# Placeholder macro written by tools/chip_assembly/macros.py
# kind: tile; a die-assembly tile at 1/4 scale less the die channel; operand in and result out registered at its spine-facing edge (the physical tile's edge registers, ot_chip_v41x_ptile NP stages); routes M2-M7 inside (obstructed), die wiring passes over it on M8/M9
VERSION 5.7 ;
BUSBITCHARS "[]" ;
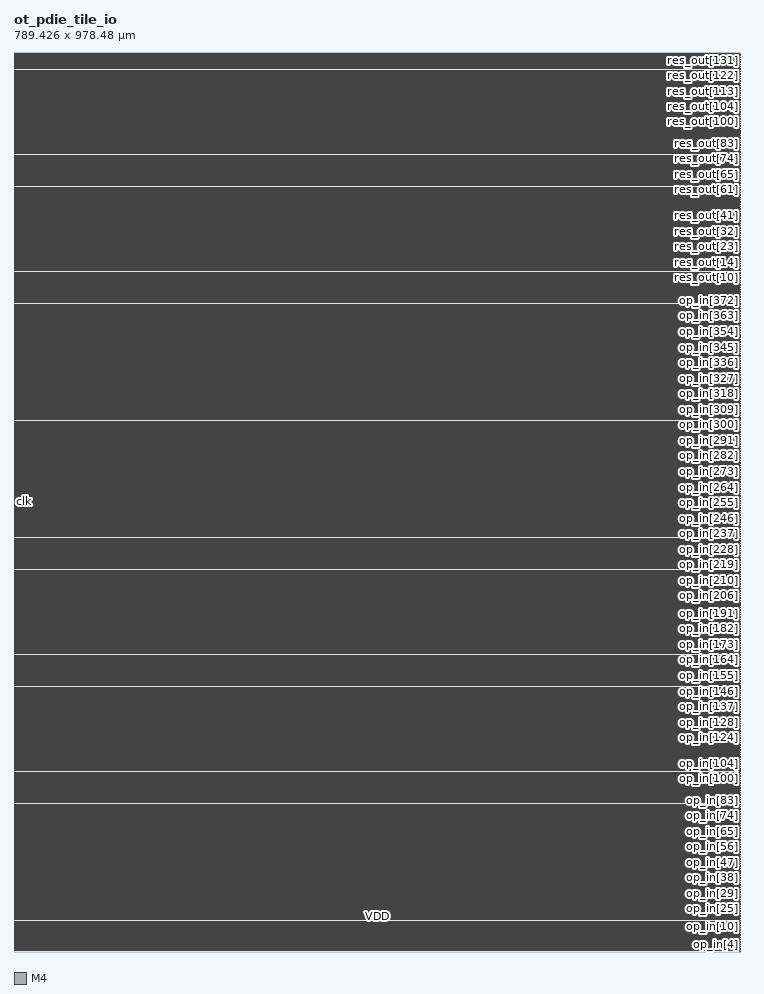
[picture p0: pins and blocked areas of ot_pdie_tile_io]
MACRO ot_pdie_tile_io
  FOREIGN ot_pdie_tile_io 0 0 ;
  SYMMETRY X Y R90 ;
  SIZE 789.426 BY 978.480 ;
  CLASS BLOCK ;
  PIN clk
    DIRECTION INPUT ;
    USE SIGNAL ;
    SHAPE ABUTMENT ;
    PORT
      LAYER M4 ;
      RECT 0.000 489.264 0.192 489.288 ;
    END
  END clk
  PIN op_in[0]
    DIRECTION INPUT ;
    USE SIGNAL ;
    SHAPE ABUTMENT ;
    PORT
      LAYER M4 ;
      RECT 789.234 0.528 789.426 0.552 ;
    END
  END op_in[0]
  PIN op_in[1]
    DIRECTION INPUT ;
    USE SIGNAL ;
    SHAPE ABUTMENT ;
    PORT
      LAYER M4 ;
      RECT 789.234 2.400 789.426 2.424 ;
    END
  END op_in[1]
  PIN op_in[2]
    DIRECTION INPUT ;
    USE SIGNAL ;
    SHAPE ABUTMENT ;
    PORT
      LAYER M4 ;
      RECT 789.234 4.272 789.426 4.296 ;
    END
  END op_in[2]
  PIN op_in[3]
    DIRECTION INPUT ;
    USE SIGNAL ;
    SHAPE ABUTMENT ;
    PORT
      LAYER M4 ;
      RECT 789.234 6.144 789.426 6.168 ;
    END
  END op_in[3]
  PIN op_in[4]
    DIRECTION INPUT ;
    USE SIGNAL ;
    SHAPE ABUTMENT ;
    PORT
      LAYER M4 ;
      RECT 789.234 8.016 789.426 8.040 ;
    END
  END op_in[4]
  PIN op_in[5]
    DIRECTION INPUT ;
    USE SIGNAL ;
    SHAPE ABUTMENT ;
    PORT
      LAYER M4 ;
      RECT 789.234 9.888 789.426 9.912 ;
    END
  END op_in[5]
  PIN op_in[6]
    DIRECTION INPUT ;
    USE SIGNAL ;
    SHAPE ABUTMENT ;
    PORT
      LAYER M4 ;
      RECT 789.234 11.760 789.426 11.784 ;
    END
  END op_in[6]
  PIN op_in[7]
    DIRECTION INPUT ;
    USE SIGNAL ;
    SHAPE ABUTMENT ;
    PORT
      LAYER M4 ;
      RECT 789.234 13.680 789.426 13.704 ;
    END
  END op_in[7]
  PIN op_in[8]
    DIRECTION INPUT ;
    USE SIGNAL ;
    SHAPE ABUTMENT ;
    PORT
      LAYER M4 ;
      RECT 789.234 15.552 789.426 15.576 ;
    END
  END op_in[8]
  PIN op_in[9]
    DIRECTION INPUT ;
    USE SIGNAL ;
    SHAPE ABUTMENT ;
    PORT
      LAYER M4 ;
      RECT 789.234 17.424 789.426 17.448 ;
    END
  END op_in[9]
  PIN op_in[10]
    DIRECTION INPUT ;
    USE SIGNAL ;
    SHAPE ABUTMENT ;
    PORT
      LAYER M4 ;
      RECT 789.234 19.296 789.426 19.320 ;
    END
  END op_in[10]
  PIN op_in[11]
    DIRECTION INPUT ;
    USE SIGNAL ;
    SHAPE ABUTMENT ;
    PORT
      LAYER M4 ;
      RECT 789.234 21.168 789.426 21.192 ;
    END
  END op_in[11]
  PIN op_in[12]
    DIRECTION INPUT ;
    USE SIGNAL ;
    SHAPE ABUTMENT ;
    PORT
      LAYER M4 ;
      RECT 789.234 23.040 789.426 23.064 ;
    END
  END op_in[12]
  PIN op_in[13]
    DIRECTION INPUT ;
    USE SIGNAL ;
    SHAPE ABUTMENT ;
    PORT
      LAYER M4 ;
      RECT 789.234 24.960 789.426 24.984 ;
    END
  END op_in[13]
  PIN op_in[14]
    DIRECTION INPUT ;
    USE SIGNAL ;
    SHAPE ABUTMENT ;
    PORT
      LAYER M4 ;
      RECT 789.234 26.832 789.426 26.856 ;
    END
  END op_in[14]
  PIN op_in[15]
    DIRECTION INPUT ;
    USE SIGNAL ;
    SHAPE ABUTMENT ;
    PORT
      LAYER M4 ;
      RECT 789.234 28.704 789.426 28.728 ;
    END
  END op_in[15]
  PIN op_in[16]
    DIRECTION INPUT ;
    USE SIGNAL ;
    SHAPE ABUTMENT ;
    PORT
      LAYER M4 ;
      RECT 789.234 30.576 789.426 30.600 ;
    END
  END op_in[16]
  PIN op_in[17]
    DIRECTION INPUT ;
    USE SIGNAL ;
    SHAPE ABUTMENT ;
    PORT
      LAYER M4 ;
      RECT 789.234 32.448 789.426 32.472 ;
    END
  END op_in[17]
  PIN op_in[18]
    DIRECTION INPUT ;
    USE SIGNAL ;
    SHAPE ABUTMENT ;
    PORT
      LAYER M4 ;
      RECT 789.234 34.320 789.426 34.344 ;
    END
  END op_in[18]
  PIN op_in[19]
    DIRECTION INPUT ;
    USE SIGNAL ;
    SHAPE ABUTMENT ;
    PORT
      LAYER M4 ;
      RECT 789.234 36.240 789.426 36.264 ;
    END
  END op_in[19]
  PIN op_in[20]
    DIRECTION INPUT ;
    USE SIGNAL ;
    SHAPE ABUTMENT ;
    PORT
      LAYER M4 ;
      RECT 789.234 38.112 789.426 38.136 ;
    END
  END op_in[20]
  PIN op_in[21]
    DIRECTION INPUT ;
    USE SIGNAL ;
    SHAPE ABUTMENT ;
    PORT
      LAYER M4 ;
      RECT 789.234 39.984 789.426 40.008 ;
    END
  END op_in[21]
  PIN op_in[22]
    DIRECTION INPUT ;
    USE SIGNAL ;
    SHAPE ABUTMENT ;
    PORT
      LAYER M4 ;
      RECT 789.234 41.856 789.426 41.880 ;
    END
  END op_in[22]
  PIN op_in[23]
    DIRECTION INPUT ;
    USE SIGNAL ;
    SHAPE ABUTMENT ;
    PORT
      LAYER M4 ;
      RECT 789.234 43.728 789.426 43.752 ;
    END
  END op_in[23]
  PIN op_in[24]
    DIRECTION INPUT ;
    USE SIGNAL ;
    SHAPE ABUTMENT ;
    PORT
      LAYER M4 ;
      RECT 789.234 45.600 789.426 45.624 ;
    END
  END op_in[24]
  PIN op_in[25]
    DIRECTION INPUT ;
    USE SIGNAL ;
    SHAPE ABUTMENT ;
    PORT
      LAYER M4 ;
      RECT 789.234 47.520 789.426 47.544 ;
    END
  END op_in[25]
  PIN op_in[26]
    DIRECTION INPUT ;
    USE SIGNAL ;
    SHAPE ABUTMENT ;
    PORT
      LAYER M4 ;
      RECT 789.234 49.392 789.426 49.416 ;
    END
  END op_in[26]
  PIN op_in[27]
    DIRECTION INPUT ;
    USE SIGNAL ;
    SHAPE ABUTMENT ;
    PORT
      LAYER M4 ;
      RECT 789.234 51.264 789.426 51.288 ;
    END
  END op_in[27]
  PIN op_in[28]
    DIRECTION INPUT ;
    USE SIGNAL ;
    SHAPE ABUTMENT ;
    PORT
      LAYER M4 ;
      RECT 789.234 53.136 789.426 53.160 ;
    END
  END op_in[28]
  PIN op_in[29]
    DIRECTION INPUT ;
    USE SIGNAL ;
    SHAPE ABUTMENT ;
    PORT
      LAYER M4 ;
      RECT 789.234 55.008 789.426 55.032 ;
    END
  END op_in[29]
  PIN op_in[30]
    DIRECTION INPUT ;
    USE SIGNAL ;
    SHAPE ABUTMENT ;
    PORT
      LAYER M4 ;
      RECT 789.234 56.880 789.426 56.904 ;
    END
  END op_in[30]
  PIN op_in[31]
    DIRECTION INPUT ;
    USE SIGNAL ;
    SHAPE ABUTMENT ;
    PORT
      LAYER M4 ;
      RECT 789.234 58.800 789.426 58.824 ;
    END
  END op_in[31]
  PIN op_in[32]
    DIRECTION INPUT ;
    USE SIGNAL ;
    SHAPE ABUTMENT ;
    PORT
      LAYER M4 ;
      RECT 789.234 60.672 789.426 60.696 ;
    END
  END op_in[32]
  PIN op_in[33]
    DIRECTION INPUT ;
    USE SIGNAL ;
    SHAPE ABUTMENT ;
    PORT
      LAYER M4 ;
      RECT 789.234 62.544 789.426 62.568 ;
    END
  END op_in[33]
  PIN op_in[34]
    DIRECTION INPUT ;
    USE SIGNAL ;
    SHAPE ABUTMENT ;
    PORT
      LAYER M4 ;
      RECT 789.234 64.416 789.426 64.440 ;
    END
  END op_in[34]
  PIN op_in[35]
    DIRECTION INPUT ;
    USE SIGNAL ;
    SHAPE ABUTMENT ;
    PORT
      LAYER M4 ;
      RECT 789.234 66.288 789.426 66.312 ;
    END
  END op_in[35]
  PIN op_in[36]
    DIRECTION INPUT ;
    USE SIGNAL ;
    SHAPE ABUTMENT ;
    PORT
      LAYER M4 ;
      RECT 789.234 68.160 789.426 68.184 ;
    END
  END op_in[36]
  PIN op_in[37]
    DIRECTION INPUT ;
    USE SIGNAL ;
    SHAPE ABUTMENT ;
    PORT
      LAYER M4 ;
      RECT 789.234 70.032 789.426 70.056 ;
    END
  END op_in[37]
  PIN op_in[38]
    DIRECTION INPUT ;
    USE SIGNAL ;
    SHAPE ABUTMENT ;
    PORT
      LAYER M4 ;
      RECT 789.234 71.952 789.426 71.976 ;
    END
  END op_in[38]
  PIN op_in[39]
    DIRECTION INPUT ;
    USE SIGNAL ;
    SHAPE ABUTMENT ;
    PORT
      LAYER M4 ;
      RECT 789.234 73.824 789.426 73.848 ;
    END
  END op_in[39]
  PIN op_in[40]
    DIRECTION INPUT ;
    USE SIGNAL ;
    SHAPE ABUTMENT ;
    PORT
      LAYER M4 ;
      RECT 789.234 75.696 789.426 75.720 ;
    END
  END op_in[40]
  PIN op_in[41]
    DIRECTION INPUT ;
    USE SIGNAL ;
    SHAPE ABUTMENT ;
    PORT
      LAYER M4 ;
      RECT 789.234 77.568 789.426 77.592 ;
    END
  END op_in[41]
  PIN op_in[42]
    DIRECTION INPUT ;
    USE SIGNAL ;
    SHAPE ABUTMENT ;
    PORT
      LAYER M4 ;
      RECT 789.234 79.440 789.426 79.464 ;
    END
  END op_in[42]
  PIN op_in[43]
    DIRECTION INPUT ;
    USE SIGNAL ;
    SHAPE ABUTMENT ;
    PORT
      LAYER M4 ;
      RECT 789.234 81.312 789.426 81.336 ;
    END
  END op_in[43]
  PIN op_in[44]
    DIRECTION INPUT ;
    USE SIGNAL ;
    SHAPE ABUTMENT ;
    PORT
      LAYER M4 ;
      RECT 789.234 83.232 789.426 83.256 ;
    END
  END op_in[44]
  PIN op_in[45]
    DIRECTION INPUT ;
    USE SIGNAL ;
    SHAPE ABUTMENT ;
    PORT
      LAYER M4 ;
      RECT 789.234 85.104 789.426 85.128 ;
    END
  END op_in[45]
  PIN op_in[46]
    DIRECTION INPUT ;
    USE SIGNAL ;
    SHAPE ABUTMENT ;
    PORT
      LAYER M4 ;
      RECT 789.234 86.976 789.426 87.000 ;
    END
  END op_in[46]
  PIN op_in[47]
    DIRECTION INPUT ;
    USE SIGNAL ;
    SHAPE ABUTMENT ;
    PORT
      LAYER M4 ;
      RECT 789.234 88.848 789.426 88.872 ;
    END
  END op_in[47]
  PIN op_in[48]
    DIRECTION INPUT ;
    USE SIGNAL ;
    SHAPE ABUTMENT ;
    PORT
      LAYER M4 ;
      RECT 789.234 90.720 789.426 90.744 ;
    END
  END op_in[48]
  PIN op_in[49]
    DIRECTION INPUT ;
    USE SIGNAL ;
    SHAPE ABUTMENT ;
    PORT
      LAYER M4 ;
      RECT 789.234 92.592 789.426 92.616 ;
    END
  END op_in[49]
  PIN op_in[50]
    DIRECTION INPUT ;
    USE SIGNAL ;
    SHAPE ABUTMENT ;
    PORT
      LAYER M4 ;
      RECT 789.234 94.512 789.426 94.536 ;
    END
  END op_in[50]
  PIN op_in[51]
    DIRECTION INPUT ;
    USE SIGNAL ;
    SHAPE ABUTMENT ;
    PORT
      LAYER M4 ;
      RECT 789.234 96.384 789.426 96.408 ;
    END
  END op_in[51]
  PIN op_in[52]
    DIRECTION INPUT ;
    USE SIGNAL ;
    SHAPE ABUTMENT ;
    PORT
      LAYER M4 ;
      RECT 789.234 98.256 789.426 98.280 ;
    END
  END op_in[52]
  PIN op_in[53]
    DIRECTION INPUT ;
    USE SIGNAL ;
    SHAPE ABUTMENT ;
    PORT
      LAYER M4 ;
      RECT 789.234 100.128 789.426 100.152 ;
    END
  END op_in[53]
  PIN op_in[54]
    DIRECTION INPUT ;
    USE SIGNAL ;
    SHAPE ABUTMENT ;
    PORT
      LAYER M4 ;
      RECT 789.234 102.000 789.426 102.024 ;
    END
  END op_in[54]
  PIN op_in[55]
    DIRECTION INPUT ;
    USE SIGNAL ;
    SHAPE ABUTMENT ;
    PORT
      LAYER M4 ;
      RECT 789.234 103.872 789.426 103.896 ;
    END
  END op_in[55]
  PIN op_in[56]
    DIRECTION INPUT ;
    USE SIGNAL ;
    SHAPE ABUTMENT ;
    PORT
      LAYER M4 ;
      RECT 789.234 105.792 789.426 105.816 ;
    END
  END op_in[56]
  PIN op_in[57]
    DIRECTION INPUT ;
    USE SIGNAL ;
    SHAPE ABUTMENT ;
    PORT
      LAYER M4 ;
      RECT 789.234 107.664 789.426 107.688 ;
    END
  END op_in[57]
  PIN op_in[58]
    DIRECTION INPUT ;
    USE SIGNAL ;
    SHAPE ABUTMENT ;
    PORT
      LAYER M4 ;
      RECT 789.234 109.536 789.426 109.560 ;
    END
  END op_in[58]
  PIN op_in[59]
    DIRECTION INPUT ;
    USE SIGNAL ;
    SHAPE ABUTMENT ;
    PORT
      LAYER M4 ;
      RECT 789.234 111.408 789.426 111.432 ;
    END
  END op_in[59]
  PIN op_in[60]
    DIRECTION INPUT ;
    USE SIGNAL ;
    SHAPE ABUTMENT ;
    PORT
      LAYER M4 ;
      RECT 789.234 113.280 789.426 113.304 ;
    END
  END op_in[60]
  PIN op_in[61]
    DIRECTION INPUT ;
    USE SIGNAL ;
    SHAPE ABUTMENT ;
    PORT
      LAYER M4 ;
      RECT 789.234 115.152 789.426 115.176 ;
    END
  END op_in[61]
  PIN op_in[62]
    DIRECTION INPUT ;
    USE SIGNAL ;
    SHAPE ABUTMENT ;
    PORT
      LAYER M4 ;
      RECT 789.234 117.072 789.426 117.096 ;
    END
  END op_in[62]
  PIN op_in[63]
    DIRECTION INPUT ;
    USE SIGNAL ;
    SHAPE ABUTMENT ;
    PORT
      LAYER M4 ;
      RECT 789.234 118.944 789.426 118.968 ;
    END
  END op_in[63]
  PIN op_in[64]
    DIRECTION INPUT ;
    USE SIGNAL ;
    SHAPE ABUTMENT ;
    PORT
      LAYER M4 ;
      RECT 789.234 120.816 789.426 120.840 ;
    END
  END op_in[64]
  PIN op_in[65]
    DIRECTION INPUT ;
    USE SIGNAL ;
    SHAPE ABUTMENT ;
    PORT
      LAYER M4 ;
      RECT 789.234 122.688 789.426 122.712 ;
    END
  END op_in[65]
  PIN op_in[66]
    DIRECTION INPUT ;
    USE SIGNAL ;
    SHAPE ABUTMENT ;
    PORT
      LAYER M4 ;
      RECT 789.234 124.560 789.426 124.584 ;
    END
  END op_in[66]
  PIN op_in[67]
    DIRECTION INPUT ;
    USE SIGNAL ;
    SHAPE ABUTMENT ;
    PORT
      LAYER M4 ;
      RECT 789.234 126.432 789.426 126.456 ;
    END
  END op_in[67]
  PIN op_in[68]
    DIRECTION INPUT ;
    USE SIGNAL ;
    SHAPE ABUTMENT ;
    PORT
      LAYER M4 ;
      RECT 789.234 128.304 789.426 128.328 ;
    END
  END op_in[68]
  PIN op_in[69]
    DIRECTION INPUT ;
    USE SIGNAL ;
    SHAPE ABUTMENT ;
    PORT
      LAYER M4 ;
      RECT 789.234 130.224 789.426 130.248 ;
    END
  END op_in[69]
  PIN op_in[70]
    DIRECTION INPUT ;
    USE SIGNAL ;
    SHAPE ABUTMENT ;
    PORT
      LAYER M4 ;
      RECT 789.234 132.096 789.426 132.120 ;
    END
  END op_in[70]
  PIN op_in[71]
    DIRECTION INPUT ;
    USE SIGNAL ;
    SHAPE ABUTMENT ;
    PORT
      LAYER M4 ;
      RECT 789.234 133.968 789.426 133.992 ;
    END
  END op_in[71]
  PIN op_in[72]
    DIRECTION INPUT ;
    USE SIGNAL ;
    SHAPE ABUTMENT ;
    PORT
      LAYER M4 ;
      RECT 789.234 135.840 789.426 135.864 ;
    END
  END op_in[72]
  PIN op_in[73]
    DIRECTION INPUT ;
    USE SIGNAL ;
    SHAPE ABUTMENT ;
    PORT
      LAYER M4 ;
      RECT 789.234 137.712 789.426 137.736 ;
    END
  END op_in[73]
  PIN op_in[74]
    DIRECTION INPUT ;
    USE SIGNAL ;
    SHAPE ABUTMENT ;
    PORT
      LAYER M4 ;
      RECT 789.234 139.584 789.426 139.608 ;
    END
  END op_in[74]
  PIN op_in[75]
    DIRECTION INPUT ;
    USE SIGNAL ;
    SHAPE ABUTMENT ;
    PORT
      LAYER M4 ;
      RECT 789.234 141.504 789.426 141.528 ;
    END
  END op_in[75]
  PIN op_in[76]
    DIRECTION INPUT ;
    USE SIGNAL ;
    SHAPE ABUTMENT ;
    PORT
      LAYER M4 ;
      RECT 789.234 143.376 789.426 143.400 ;
    END
  END op_in[76]
  PIN op_in[77]
    DIRECTION INPUT ;
    USE SIGNAL ;
    SHAPE ABUTMENT ;
    PORT
      LAYER M4 ;
      RECT 789.234 145.248 789.426 145.272 ;
    END
  END op_in[77]
  PIN op_in[78]
    DIRECTION INPUT ;
    USE SIGNAL ;
    SHAPE ABUTMENT ;
    PORT
      LAYER M4 ;
      RECT 789.234 147.120 789.426 147.144 ;
    END
  END op_in[78]
  PIN op_in[79]
    DIRECTION INPUT ;
    USE SIGNAL ;
    SHAPE ABUTMENT ;
    PORT
      LAYER M4 ;
      RECT 789.234 148.992 789.426 149.016 ;
    END
  END op_in[79]
  PIN op_in[80]
    DIRECTION INPUT ;
    USE SIGNAL ;
    SHAPE ABUTMENT ;
    PORT
      LAYER M4 ;
      RECT 789.234 150.864 789.426 150.888 ;
    END
  END op_in[80]
  PIN op_in[81]
    DIRECTION INPUT ;
    USE SIGNAL ;
    SHAPE ABUTMENT ;
    PORT
      LAYER M4 ;
      RECT 789.234 152.784 789.426 152.808 ;
    END
  END op_in[81]
  PIN op_in[82]
    DIRECTION INPUT ;
    USE SIGNAL ;
    SHAPE ABUTMENT ;
    PORT
      LAYER M4 ;
      RECT 789.234 154.656 789.426 154.680 ;
    END
  END op_in[82]
  PIN op_in[83]
    DIRECTION INPUT ;
    USE SIGNAL ;
    SHAPE ABUTMENT ;
    PORT
      LAYER M4 ;
      RECT 789.234 156.528 789.426 156.552 ;
    END
  END op_in[83]
  PIN op_in[84]
    DIRECTION INPUT ;
    USE SIGNAL ;
    SHAPE ABUTMENT ;
    PORT
      LAYER M4 ;
      RECT 789.234 158.400 789.426 158.424 ;
    END
  END op_in[84]
  PIN op_in[85]
    DIRECTION INPUT ;
    USE SIGNAL ;
    SHAPE ABUTMENT ;
    PORT
      LAYER M4 ;
      RECT 789.234 160.272 789.426 160.296 ;
    END
  END op_in[85]
  PIN op_in[86]
    DIRECTION INPUT ;
    USE SIGNAL ;
    SHAPE ABUTMENT ;
    PORT
      LAYER M4 ;
      RECT 789.234 162.144 789.426 162.168 ;
    END
  END op_in[86]
  PIN op_in[87]
    DIRECTION INPUT ;
    USE SIGNAL ;
    SHAPE ABUTMENT ;
    PORT
      LAYER M4 ;
      RECT 789.234 164.064 789.426 164.088 ;
    END
  END op_in[87]
  PIN op_in[88]
    DIRECTION INPUT ;
    USE SIGNAL ;
    SHAPE ABUTMENT ;
    PORT
      LAYER M4 ;
      RECT 789.234 165.936 789.426 165.960 ;
    END
  END op_in[88]
  PIN op_in[89]
    DIRECTION INPUT ;
    USE SIGNAL ;
    SHAPE ABUTMENT ;
    PORT
      LAYER M4 ;
      RECT 789.234 167.808 789.426 167.832 ;
    END
  END op_in[89]
  PIN op_in[90]
    DIRECTION INPUT ;
    USE SIGNAL ;
    SHAPE ABUTMENT ;
    PORT
      LAYER M4 ;
      RECT 789.234 169.680 789.426 169.704 ;
    END
  END op_in[90]
  PIN op_in[91]
    DIRECTION INPUT ;
    USE SIGNAL ;
    SHAPE ABUTMENT ;
    PORT
      LAYER M4 ;
      RECT 789.234 171.552 789.426 171.576 ;
    END
  END op_in[91]
  PIN op_in[92]
    DIRECTION INPUT ;
    USE SIGNAL ;
    SHAPE ABUTMENT ;
    PORT
      LAYER M4 ;
      RECT 789.234 173.424 789.426 173.448 ;
    END
  END op_in[92]
  PIN op_in[93]
    DIRECTION INPUT ;
    USE SIGNAL ;
    SHAPE ABUTMENT ;
    PORT
      LAYER M4 ;
      RECT 789.234 175.344 789.426 175.368 ;
    END
  END op_in[93]
  PIN op_in[94]
    DIRECTION INPUT ;
    USE SIGNAL ;
    SHAPE ABUTMENT ;
    PORT
      LAYER M4 ;
      RECT 789.234 177.216 789.426 177.240 ;
    END
  END op_in[94]
  PIN op_in[95]
    DIRECTION INPUT ;
    USE SIGNAL ;
    SHAPE ABUTMENT ;
    PORT
      LAYER M4 ;
      RECT 789.234 179.088 789.426 179.112 ;
    END
  END op_in[95]
  PIN op_in[96]
    DIRECTION INPUT ;
    USE SIGNAL ;
    SHAPE ABUTMENT ;
    PORT
      LAYER M4 ;
      RECT 789.234 180.960 789.426 180.984 ;
    END
  END op_in[96]
  PIN op_in[97]
    DIRECTION INPUT ;
    USE SIGNAL ;
    SHAPE ABUTMENT ;
    PORT
      LAYER M4 ;
      RECT 789.234 182.832 789.426 182.856 ;
    END
  END op_in[97]
  PIN op_in[98]
    DIRECTION INPUT ;
    USE SIGNAL ;
    SHAPE ABUTMENT ;
    PORT
      LAYER M4 ;
      RECT 789.234 184.704 789.426 184.728 ;
    END
  END op_in[98]
  PIN op_in[99]
    DIRECTION INPUT ;
    USE SIGNAL ;
    SHAPE ABUTMENT ;
    PORT
      LAYER M4 ;
      RECT 789.234 186.576 789.426 186.600 ;
    END
  END op_in[99]
  PIN op_in[100]
    DIRECTION INPUT ;
    USE SIGNAL ;
    SHAPE ABUTMENT ;
    PORT
      LAYER M4 ;
      RECT 789.234 188.496 789.426 188.520 ;
    END
  END op_in[100]
  PIN op_in[101]
    DIRECTION INPUT ;
    USE SIGNAL ;
    SHAPE ABUTMENT ;
    PORT
      LAYER M4 ;
      RECT 789.234 190.368 789.426 190.392 ;
    END
  END op_in[101]
  PIN op_in[102]
    DIRECTION INPUT ;
    USE SIGNAL ;
    SHAPE ABUTMENT ;
    PORT
      LAYER M4 ;
      RECT 789.234 192.240 789.426 192.264 ;
    END
  END op_in[102]
  PIN op_in[103]
    DIRECTION INPUT ;
    USE SIGNAL ;
    SHAPE ABUTMENT ;
    PORT
      LAYER M4 ;
      RECT 789.234 194.112 789.426 194.136 ;
    END
  END op_in[103]
  PIN op_in[104]
    DIRECTION INPUT ;
    USE SIGNAL ;
    SHAPE ABUTMENT ;
    PORT
      LAYER M4 ;
      RECT 789.234 195.984 789.426 196.008 ;
    END
  END op_in[104]
  PIN op_in[105]
    DIRECTION INPUT ;
    USE SIGNAL ;
    SHAPE ABUTMENT ;
    PORT
      LAYER M4 ;
      RECT 789.234 197.856 789.426 197.880 ;
    END
  END op_in[105]
  PIN op_in[106]
    DIRECTION INPUT ;
    USE SIGNAL ;
    SHAPE ABUTMENT ;
    PORT
      LAYER M4 ;
      RECT 789.234 199.776 789.426 199.800 ;
    END
  END op_in[106]
  PIN op_in[107]
    DIRECTION INPUT ;
    USE SIGNAL ;
    SHAPE ABUTMENT ;
    PORT
      LAYER M4 ;
      RECT 789.234 201.648 789.426 201.672 ;
    END
  END op_in[107]
  PIN op_in[108]
    DIRECTION INPUT ;
    USE SIGNAL ;
    SHAPE ABUTMENT ;
    PORT
      LAYER M4 ;
      RECT 789.234 203.520 789.426 203.544 ;
    END
  END op_in[108]
  PIN op_in[109]
    DIRECTION INPUT ;
    USE SIGNAL ;
    SHAPE ABUTMENT ;
    PORT
      LAYER M4 ;
      RECT 789.234 205.392 789.426 205.416 ;
    END
  END op_in[109]
  PIN op_in[110]
    DIRECTION INPUT ;
    USE SIGNAL ;
    SHAPE ABUTMENT ;
    PORT
      LAYER M4 ;
      RECT 789.234 207.264 789.426 207.288 ;
    END
  END op_in[110]
  PIN op_in[111]
    DIRECTION INPUT ;
    USE SIGNAL ;
    SHAPE ABUTMENT ;
    PORT
      LAYER M4 ;
      RECT 789.234 209.136 789.426 209.160 ;
    END
  END op_in[111]
  PIN op_in[112]
    DIRECTION INPUT ;
    USE SIGNAL ;
    SHAPE ABUTMENT ;
    PORT
      LAYER M4 ;
      RECT 789.234 211.056 789.426 211.080 ;
    END
  END op_in[112]
  PIN op_in[113]
    DIRECTION INPUT ;
    USE SIGNAL ;
    SHAPE ABUTMENT ;
    PORT
      LAYER M4 ;
      RECT 789.234 212.928 789.426 212.952 ;
    END
  END op_in[113]
  PIN op_in[114]
    DIRECTION INPUT ;
    USE SIGNAL ;
    SHAPE ABUTMENT ;
    PORT
      LAYER M4 ;
      RECT 789.234 214.800 789.426 214.824 ;
    END
  END op_in[114]
  PIN op_in[115]
    DIRECTION INPUT ;
    USE SIGNAL ;
    SHAPE ABUTMENT ;
    PORT
      LAYER M4 ;
      RECT 789.234 216.672 789.426 216.696 ;
    END
  END op_in[115]
  PIN op_in[116]
    DIRECTION INPUT ;
    USE SIGNAL ;
    SHAPE ABUTMENT ;
    PORT
      LAYER M4 ;
      RECT 789.234 218.544 789.426 218.568 ;
    END
  END op_in[116]
  PIN op_in[117]
    DIRECTION INPUT ;
    USE SIGNAL ;
    SHAPE ABUTMENT ;
    PORT
      LAYER M4 ;
      RECT 789.234 220.416 789.426 220.440 ;
    END
  END op_in[117]
  PIN op_in[118]
    DIRECTION INPUT ;
    USE SIGNAL ;
    SHAPE ABUTMENT ;
    PORT
      LAYER M4 ;
      RECT 789.234 222.336 789.426 222.360 ;
    END
  END op_in[118]
  PIN op_in[119]
    DIRECTION INPUT ;
    USE SIGNAL ;
    SHAPE ABUTMENT ;
    PORT
      LAYER M4 ;
      RECT 789.234 224.208 789.426 224.232 ;
    END
  END op_in[119]
  PIN op_in[120]
    DIRECTION INPUT ;
    USE SIGNAL ;
    SHAPE ABUTMENT ;
    PORT
      LAYER M4 ;
      RECT 789.234 226.080 789.426 226.104 ;
    END
  END op_in[120]
  PIN op_in[121]
    DIRECTION INPUT ;
    USE SIGNAL ;
    SHAPE ABUTMENT ;
    PORT
      LAYER M4 ;
      RECT 789.234 227.952 789.426 227.976 ;
    END
  END op_in[121]
  PIN op_in[122]
    DIRECTION INPUT ;
    USE SIGNAL ;
    SHAPE ABUTMENT ;
    PORT
      LAYER M4 ;
      RECT 789.234 229.824 789.426 229.848 ;
    END
  END op_in[122]
  PIN op_in[123]
    DIRECTION INPUT ;
    USE SIGNAL ;
    SHAPE ABUTMENT ;
    PORT
      LAYER M4 ;
      RECT 789.234 231.696 789.426 231.720 ;
    END
  END op_in[123]
  PIN op_in[124]
    DIRECTION INPUT ;
    USE SIGNAL ;
    SHAPE ABUTMENT ;
    PORT
      LAYER M4 ;
      RECT 789.234 233.616 789.426 233.640 ;
    END
  END op_in[124]
  PIN op_in[125]
    DIRECTION INPUT ;
    USE SIGNAL ;
    SHAPE ABUTMENT ;
    PORT
      LAYER M4 ;
      RECT 789.234 235.488 789.426 235.512 ;
    END
  END op_in[125]
  PIN op_in[126]
    DIRECTION INPUT ;
    USE SIGNAL ;
    SHAPE ABUTMENT ;
    PORT
      LAYER M4 ;
      RECT 789.234 237.360 789.426 237.384 ;
    END
  END op_in[126]
  PIN op_in[127]
    DIRECTION INPUT ;
    USE SIGNAL ;
    SHAPE ABUTMENT ;
    PORT
      LAYER M4 ;
      RECT 789.234 239.232 789.426 239.256 ;
    END
  END op_in[127]
  PIN op_in[128]
    DIRECTION INPUT ;
    USE SIGNAL ;
    SHAPE ABUTMENT ;
    PORT
      LAYER M4 ;
      RECT 789.234 241.104 789.426 241.128 ;
    END
  END op_in[128]
  PIN op_in[129]
    DIRECTION INPUT ;
    USE SIGNAL ;
    SHAPE ABUTMENT ;
    PORT
      LAYER M4 ;
      RECT 789.234 242.976 789.426 243.000 ;
    END
  END op_in[129]
  PIN op_in[130]
    DIRECTION INPUT ;
    USE SIGNAL ;
    SHAPE ABUTMENT ;
    PORT
      LAYER M4 ;
      RECT 789.234 244.896 789.426 244.920 ;
    END
  END op_in[130]
  PIN op_in[131]
    DIRECTION INPUT ;
    USE SIGNAL ;
    SHAPE ABUTMENT ;
    PORT
      LAYER M4 ;
      RECT 789.234 246.768 789.426 246.792 ;
    END
  END op_in[131]
  PIN op_in[132]
    DIRECTION INPUT ;
    USE SIGNAL ;
    SHAPE ABUTMENT ;
    PORT
      LAYER M4 ;
      RECT 789.234 248.640 789.426 248.664 ;
    END
  END op_in[132]
  PIN op_in[133]
    DIRECTION INPUT ;
    USE SIGNAL ;
    SHAPE ABUTMENT ;
    PORT
      LAYER M4 ;
      RECT 789.234 250.512 789.426 250.536 ;
    END
  END op_in[133]
  PIN op_in[134]
    DIRECTION INPUT ;
    USE SIGNAL ;
    SHAPE ABUTMENT ;
    PORT
      LAYER M4 ;
      RECT 789.234 252.384 789.426 252.408 ;
    END
  END op_in[134]
  PIN op_in[135]
    DIRECTION INPUT ;
    USE SIGNAL ;
    SHAPE ABUTMENT ;
    PORT
      LAYER M4 ;
      RECT 789.234 254.256 789.426 254.280 ;
    END
  END op_in[135]
  PIN op_in[136]
    DIRECTION INPUT ;
    USE SIGNAL ;
    SHAPE ABUTMENT ;
    PORT
      LAYER M4 ;
      RECT 789.234 256.128 789.426 256.152 ;
    END
  END op_in[136]
  PIN op_in[137]
    DIRECTION INPUT ;
    USE SIGNAL ;
    SHAPE ABUTMENT ;
    PORT
      LAYER M4 ;
      RECT 789.234 258.048 789.426 258.072 ;
    END
  END op_in[137]
  PIN op_in[138]
    DIRECTION INPUT ;
    USE SIGNAL ;
    SHAPE ABUTMENT ;
    PORT
      LAYER M4 ;
      RECT 789.234 259.920 789.426 259.944 ;
    END
  END op_in[138]
  PIN op_in[139]
    DIRECTION INPUT ;
    USE SIGNAL ;
    SHAPE ABUTMENT ;
    PORT
      LAYER M4 ;
      RECT 789.234 261.792 789.426 261.816 ;
    END
  END op_in[139]
  PIN op_in[140]
    DIRECTION INPUT ;
    USE SIGNAL ;
    SHAPE ABUTMENT ;
    PORT
      LAYER M4 ;
      RECT 789.234 263.664 789.426 263.688 ;
    END
  END op_in[140]
  PIN op_in[141]
    DIRECTION INPUT ;
    USE SIGNAL ;
    SHAPE ABUTMENT ;
    PORT
      LAYER M4 ;
      RECT 789.234 265.536 789.426 265.560 ;
    END
  END op_in[141]
  PIN op_in[142]
    DIRECTION INPUT ;
    USE SIGNAL ;
    SHAPE ABUTMENT ;
    PORT
      LAYER M4 ;
      RECT 789.234 267.408 789.426 267.432 ;
    END
  END op_in[142]
  PIN op_in[143]
    DIRECTION INPUT ;
    USE SIGNAL ;
    SHAPE ABUTMENT ;
    PORT
      LAYER M4 ;
      RECT 789.234 269.328 789.426 269.352 ;
    END
  END op_in[143]
  PIN op_in[144]
    DIRECTION INPUT ;
    USE SIGNAL ;
    SHAPE ABUTMENT ;
    PORT
      LAYER M4 ;
      RECT 789.234 271.200 789.426 271.224 ;
    END
  END op_in[144]
  PIN op_in[145]
    DIRECTION INPUT ;
    USE SIGNAL ;
    SHAPE ABUTMENT ;
    PORT
      LAYER M4 ;
      RECT 789.234 273.072 789.426 273.096 ;
    END
  END op_in[145]
  PIN op_in[146]
    DIRECTION INPUT ;
    USE SIGNAL ;
    SHAPE ABUTMENT ;
    PORT
      LAYER M4 ;
      RECT 789.234 274.944 789.426 274.968 ;
    END
  END op_in[146]
  PIN op_in[147]
    DIRECTION INPUT ;
    USE SIGNAL ;
    SHAPE ABUTMENT ;
    PORT
      LAYER M4 ;
      RECT 789.234 276.816 789.426 276.840 ;
    END
  END op_in[147]
  PIN op_in[148]
    DIRECTION INPUT ;
    USE SIGNAL ;
    SHAPE ABUTMENT ;
    PORT
      LAYER M4 ;
      RECT 789.234 278.688 789.426 278.712 ;
    END
  END op_in[148]
  PIN op_in[149]
    DIRECTION INPUT ;
    USE SIGNAL ;
    SHAPE ABUTMENT ;
    PORT
      LAYER M4 ;
      RECT 789.234 280.608 789.426 280.632 ;
    END
  END op_in[149]
  PIN op_in[150]
    DIRECTION INPUT ;
    USE SIGNAL ;
    SHAPE ABUTMENT ;
    PORT
      LAYER M4 ;
      RECT 789.234 282.480 789.426 282.504 ;
    END
  END op_in[150]
  PIN op_in[151]
    DIRECTION INPUT ;
    USE SIGNAL ;
    SHAPE ABUTMENT ;
    PORT
      LAYER M4 ;
      RECT 789.234 284.352 789.426 284.376 ;
    END
  END op_in[151]
  PIN op_in[152]
    DIRECTION INPUT ;
    USE SIGNAL ;
    SHAPE ABUTMENT ;
    PORT
      LAYER M4 ;
      RECT 789.234 286.224 789.426 286.248 ;
    END
  END op_in[152]
  PIN op_in[153]
    DIRECTION INPUT ;
    USE SIGNAL ;
    SHAPE ABUTMENT ;
    PORT
      LAYER M4 ;
      RECT 789.234 288.096 789.426 288.120 ;
    END
  END op_in[153]
  PIN op_in[154]
    DIRECTION INPUT ;
    USE SIGNAL ;
    SHAPE ABUTMENT ;
    PORT
      LAYER M4 ;
      RECT 789.234 289.968 789.426 289.992 ;
    END
  END op_in[154]
  PIN op_in[155]
    DIRECTION INPUT ;
    USE SIGNAL ;
    SHAPE ABUTMENT ;
    PORT
      LAYER M4 ;
      RECT 789.234 291.888 789.426 291.912 ;
    END
  END op_in[155]
  PIN op_in[156]
    DIRECTION INPUT ;
    USE SIGNAL ;
    SHAPE ABUTMENT ;
    PORT
      LAYER M4 ;
      RECT 789.234 293.760 789.426 293.784 ;
    END
  END op_in[156]
  PIN op_in[157]
    DIRECTION INPUT ;
    USE SIGNAL ;
    SHAPE ABUTMENT ;
    PORT
      LAYER M4 ;
      RECT 789.234 295.632 789.426 295.656 ;
    END
  END op_in[157]
  PIN op_in[158]
    DIRECTION INPUT ;
    USE SIGNAL ;
    SHAPE ABUTMENT ;
    PORT
      LAYER M4 ;
      RECT 789.234 297.504 789.426 297.528 ;
    END
  END op_in[158]
  PIN op_in[159]
    DIRECTION INPUT ;
    USE SIGNAL ;
    SHAPE ABUTMENT ;
    PORT
      LAYER M4 ;
      RECT 789.234 299.376 789.426 299.400 ;
    END
  END op_in[159]
  PIN op_in[160]
    DIRECTION INPUT ;
    USE SIGNAL ;
    SHAPE ABUTMENT ;
    PORT
      LAYER M4 ;
      RECT 789.234 301.248 789.426 301.272 ;
    END
  END op_in[160]
  PIN op_in[161]
    DIRECTION INPUT ;
    USE SIGNAL ;
    SHAPE ABUTMENT ;
    PORT
      LAYER M4 ;
      RECT 789.234 303.168 789.426 303.192 ;
    END
  END op_in[161]
  PIN op_in[162]
    DIRECTION INPUT ;
    USE SIGNAL ;
    SHAPE ABUTMENT ;
    PORT
      LAYER M4 ;
      RECT 789.234 305.040 789.426 305.064 ;
    END
  END op_in[162]
  PIN op_in[163]
    DIRECTION INPUT ;
    USE SIGNAL ;
    SHAPE ABUTMENT ;
    PORT
      LAYER M4 ;
      RECT 789.234 306.912 789.426 306.936 ;
    END
  END op_in[163]
  PIN op_in[164]
    DIRECTION INPUT ;
    USE SIGNAL ;
    SHAPE ABUTMENT ;
    PORT
      LAYER M4 ;
      RECT 789.234 308.784 789.426 308.808 ;
    END
  END op_in[164]
  PIN op_in[165]
    DIRECTION INPUT ;
    USE SIGNAL ;
    SHAPE ABUTMENT ;
    PORT
      LAYER M4 ;
      RECT 789.234 310.656 789.426 310.680 ;
    END
  END op_in[165]
  PIN op_in[166]
    DIRECTION INPUT ;
    USE SIGNAL ;
    SHAPE ABUTMENT ;
    PORT
      LAYER M4 ;
      RECT 789.234 312.528 789.426 312.552 ;
    END
  END op_in[166]
  PIN op_in[167]
    DIRECTION INPUT ;
    USE SIGNAL ;
    SHAPE ABUTMENT ;
    PORT
      LAYER M4 ;
      RECT 789.234 314.400 789.426 314.424 ;
    END
  END op_in[167]
  PIN op_in[168]
    DIRECTION INPUT ;
    USE SIGNAL ;
    SHAPE ABUTMENT ;
    PORT
      LAYER M4 ;
      RECT 789.234 316.320 789.426 316.344 ;
    END
  END op_in[168]
  PIN op_in[169]
    DIRECTION INPUT ;
    USE SIGNAL ;
    SHAPE ABUTMENT ;
    PORT
      LAYER M4 ;
      RECT 789.234 318.192 789.426 318.216 ;
    END
  END op_in[169]
  PIN op_in[170]
    DIRECTION INPUT ;
    USE SIGNAL ;
    SHAPE ABUTMENT ;
    PORT
      LAYER M4 ;
      RECT 789.234 320.064 789.426 320.088 ;
    END
  END op_in[170]
  PIN op_in[171]
    DIRECTION INPUT ;
    USE SIGNAL ;
    SHAPE ABUTMENT ;
    PORT
      LAYER M4 ;
      RECT 789.234 321.936 789.426 321.960 ;
    END
  END op_in[171]
  PIN op_in[172]
    DIRECTION INPUT ;
    USE SIGNAL ;
    SHAPE ABUTMENT ;
    PORT
      LAYER M4 ;
      RECT 789.234 323.808 789.426 323.832 ;
    END
  END op_in[172]
  PIN op_in[173]
    DIRECTION INPUT ;
    USE SIGNAL ;
    SHAPE ABUTMENT ;
    PORT
      LAYER M4 ;
      RECT 789.234 325.680 789.426 325.704 ;
    END
  END op_in[173]
  PIN op_in[174]
    DIRECTION INPUT ;
    USE SIGNAL ;
    SHAPE ABUTMENT ;
    PORT
      LAYER M4 ;
      RECT 789.234 327.600 789.426 327.624 ;
    END
  END op_in[174]
  PIN op_in[175]
    DIRECTION INPUT ;
    USE SIGNAL ;
    SHAPE ABUTMENT ;
    PORT
      LAYER M4 ;
      RECT 789.234 329.472 789.426 329.496 ;
    END
  END op_in[175]
  PIN op_in[176]
    DIRECTION INPUT ;
    USE SIGNAL ;
    SHAPE ABUTMENT ;
    PORT
      LAYER M4 ;
      RECT 789.234 331.344 789.426 331.368 ;
    END
  END op_in[176]
  PIN op_in[177]
    DIRECTION INPUT ;
    USE SIGNAL ;
    SHAPE ABUTMENT ;
    PORT
      LAYER M4 ;
      RECT 789.234 333.216 789.426 333.240 ;
    END
  END op_in[177]
  PIN op_in[178]
    DIRECTION INPUT ;
    USE SIGNAL ;
    SHAPE ABUTMENT ;
    PORT
      LAYER M4 ;
      RECT 789.234 335.088 789.426 335.112 ;
    END
  END op_in[178]
  PIN op_in[179]
    DIRECTION INPUT ;
    USE SIGNAL ;
    SHAPE ABUTMENT ;
    PORT
      LAYER M4 ;
      RECT 789.234 336.960 789.426 336.984 ;
    END
  END op_in[179]
  PIN op_in[180]
    DIRECTION INPUT ;
    USE SIGNAL ;
    SHAPE ABUTMENT ;
    PORT
      LAYER M4 ;
      RECT 789.234 338.880 789.426 338.904 ;
    END
  END op_in[180]
  PIN op_in[181]
    DIRECTION INPUT ;
    USE SIGNAL ;
    SHAPE ABUTMENT ;
    PORT
      LAYER M4 ;
      RECT 789.234 340.752 789.426 340.776 ;
    END
  END op_in[181]
  PIN op_in[182]
    DIRECTION INPUT ;
    USE SIGNAL ;
    SHAPE ABUTMENT ;
    PORT
      LAYER M4 ;
      RECT 789.234 342.624 789.426 342.648 ;
    END
  END op_in[182]
  PIN op_in[183]
    DIRECTION INPUT ;
    USE SIGNAL ;
    SHAPE ABUTMENT ;
    PORT
      LAYER M4 ;
      RECT 789.234 344.496 789.426 344.520 ;
    END
  END op_in[183]
  PIN op_in[184]
    DIRECTION INPUT ;
    USE SIGNAL ;
    SHAPE ABUTMENT ;
    PORT
      LAYER M4 ;
      RECT 789.234 346.368 789.426 346.392 ;
    END
  END op_in[184]
  PIN op_in[185]
    DIRECTION INPUT ;
    USE SIGNAL ;
    SHAPE ABUTMENT ;
    PORT
      LAYER M4 ;
      RECT 789.234 348.240 789.426 348.264 ;
    END
  END op_in[185]
  PIN op_in[186]
    DIRECTION INPUT ;
    USE SIGNAL ;
    SHAPE ABUTMENT ;
    PORT
      LAYER M4 ;
      RECT 789.234 350.160 789.426 350.184 ;
    END
  END op_in[186]
  PIN op_in[187]
    DIRECTION INPUT ;
    USE SIGNAL ;
    SHAPE ABUTMENT ;
    PORT
      LAYER M4 ;
      RECT 789.234 352.032 789.426 352.056 ;
    END
  END op_in[187]
  PIN op_in[188]
    DIRECTION INPUT ;
    USE SIGNAL ;
    SHAPE ABUTMENT ;
    PORT
      LAYER M4 ;
      RECT 789.234 353.904 789.426 353.928 ;
    END
  END op_in[188]
  PIN op_in[189]
    DIRECTION INPUT ;
    USE SIGNAL ;
    SHAPE ABUTMENT ;
    PORT
      LAYER M4 ;
      RECT 789.234 355.776 789.426 355.800 ;
    END
  END op_in[189]
  PIN op_in[190]
    DIRECTION INPUT ;
    USE SIGNAL ;
    SHAPE ABUTMENT ;
    PORT
      LAYER M4 ;
      RECT 789.234 357.648 789.426 357.672 ;
    END
  END op_in[190]
  PIN op_in[191]
    DIRECTION INPUT ;
    USE SIGNAL ;
    SHAPE ABUTMENT ;
    PORT
      LAYER M4 ;
      RECT 789.234 359.520 789.426 359.544 ;
    END
  END op_in[191]
  PIN op_in[192]
    DIRECTION INPUT ;
    USE SIGNAL ;
    SHAPE ABUTMENT ;
    PORT
      LAYER M4 ;
      RECT 789.234 361.440 789.426 361.464 ;
    END
  END op_in[192]
  PIN op_in[193]
    DIRECTION INPUT ;
    USE SIGNAL ;
    SHAPE ABUTMENT ;
    PORT
      LAYER M4 ;
      RECT 789.234 363.312 789.426 363.336 ;
    END
  END op_in[193]
  PIN op_in[194]
    DIRECTION INPUT ;
    USE SIGNAL ;
    SHAPE ABUTMENT ;
    PORT
      LAYER M4 ;
      RECT 789.234 365.184 789.426 365.208 ;
    END
  END op_in[194]
  PIN op_in[195]
    DIRECTION INPUT ;
    USE SIGNAL ;
    SHAPE ABUTMENT ;
    PORT
      LAYER M4 ;
      RECT 789.234 367.056 789.426 367.080 ;
    END
  END op_in[195]
  PIN op_in[196]
    DIRECTION INPUT ;
    USE SIGNAL ;
    SHAPE ABUTMENT ;
    PORT
      LAYER M4 ;
      RECT 789.234 368.928 789.426 368.952 ;
    END
  END op_in[196]
  PIN op_in[197]
    DIRECTION INPUT ;
    USE SIGNAL ;
    SHAPE ABUTMENT ;
    PORT
      LAYER M4 ;
      RECT 789.234 370.800 789.426 370.824 ;
    END
  END op_in[197]
  PIN op_in[198]
    DIRECTION INPUT ;
    USE SIGNAL ;
    SHAPE ABUTMENT ;
    PORT
      LAYER M4 ;
      RECT 789.234 372.672 789.426 372.696 ;
    END
  END op_in[198]
  PIN op_in[199]
    DIRECTION INPUT ;
    USE SIGNAL ;
    SHAPE ABUTMENT ;
    PORT
      LAYER M4 ;
      RECT 789.234 374.592 789.426 374.616 ;
    END
  END op_in[199]
  PIN op_in[200]
    DIRECTION INPUT ;
    USE SIGNAL ;
    SHAPE ABUTMENT ;
    PORT
      LAYER M4 ;
      RECT 789.234 376.464 789.426 376.488 ;
    END
  END op_in[200]
  PIN op_in[201]
    DIRECTION INPUT ;
    USE SIGNAL ;
    SHAPE ABUTMENT ;
    PORT
      LAYER M4 ;
      RECT 789.234 378.336 789.426 378.360 ;
    END
  END op_in[201]
  PIN op_in[202]
    DIRECTION INPUT ;
    USE SIGNAL ;
    SHAPE ABUTMENT ;
    PORT
      LAYER M4 ;
      RECT 789.234 380.208 789.426 380.232 ;
    END
  END op_in[202]
  PIN op_in[203]
    DIRECTION INPUT ;
    USE SIGNAL ;
    SHAPE ABUTMENT ;
    PORT
      LAYER M4 ;
      RECT 789.234 382.080 789.426 382.104 ;
    END
  END op_in[203]
  PIN op_in[204]
    DIRECTION INPUT ;
    USE SIGNAL ;
    SHAPE ABUTMENT ;
    PORT
      LAYER M4 ;
      RECT 789.234 383.952 789.426 383.976 ;
    END
  END op_in[204]
  PIN op_in[205]
    DIRECTION INPUT ;
    USE SIGNAL ;
    SHAPE ABUTMENT ;
    PORT
      LAYER M4 ;
      RECT 789.234 385.872 789.426 385.896 ;
    END
  END op_in[205]
  PIN op_in[206]
    DIRECTION INPUT ;
    USE SIGNAL ;
    SHAPE ABUTMENT ;
    PORT
      LAYER M4 ;
      RECT 789.234 387.744 789.426 387.768 ;
    END
  END op_in[206]
  PIN op_in[207]
    DIRECTION INPUT ;
    USE SIGNAL ;
    SHAPE ABUTMENT ;
    PORT
      LAYER M4 ;
      RECT 789.234 389.616 789.426 389.640 ;
    END
  END op_in[207]
  PIN op_in[208]
    DIRECTION INPUT ;
    USE SIGNAL ;
    SHAPE ABUTMENT ;
    PORT
      LAYER M4 ;
      RECT 789.234 391.488 789.426 391.512 ;
    END
  END op_in[208]
  PIN op_in[209]
    DIRECTION INPUT ;
    USE SIGNAL ;
    SHAPE ABUTMENT ;
    PORT
      LAYER M4 ;
      RECT 789.234 393.360 789.426 393.384 ;
    END
  END op_in[209]
  PIN op_in[210]
    DIRECTION INPUT ;
    USE SIGNAL ;
    SHAPE ABUTMENT ;
    PORT
      LAYER M4 ;
      RECT 789.234 395.232 789.426 395.256 ;
    END
  END op_in[210]
  PIN op_in[211]
    DIRECTION INPUT ;
    USE SIGNAL ;
    SHAPE ABUTMENT ;
    PORT
      LAYER M4 ;
      RECT 789.234 397.152 789.426 397.176 ;
    END
  END op_in[211]
  PIN op_in[212]
    DIRECTION INPUT ;
    USE SIGNAL ;
    SHAPE ABUTMENT ;
    PORT
      LAYER M4 ;
      RECT 789.234 399.024 789.426 399.048 ;
    END
  END op_in[212]
  PIN op_in[213]
    DIRECTION INPUT ;
    USE SIGNAL ;
    SHAPE ABUTMENT ;
    PORT
      LAYER M4 ;
      RECT 789.234 400.896 789.426 400.920 ;
    END
  END op_in[213]
  PIN op_in[214]
    DIRECTION INPUT ;
    USE SIGNAL ;
    SHAPE ABUTMENT ;
    PORT
      LAYER M4 ;
      RECT 789.234 402.768 789.426 402.792 ;
    END
  END op_in[214]
  PIN op_in[215]
    DIRECTION INPUT ;
    USE SIGNAL ;
    SHAPE ABUTMENT ;
    PORT
      LAYER M4 ;
      RECT 789.234 404.640 789.426 404.664 ;
    END
  END op_in[215]
  PIN op_in[216]
    DIRECTION INPUT ;
    USE SIGNAL ;
    SHAPE ABUTMENT ;
    PORT
      LAYER M4 ;
      RECT 789.234 406.512 789.426 406.536 ;
    END
  END op_in[216]
  PIN op_in[217]
    DIRECTION INPUT ;
    USE SIGNAL ;
    SHAPE ABUTMENT ;
    PORT
      LAYER M4 ;
      RECT 789.234 408.432 789.426 408.456 ;
    END
  END op_in[217]
  PIN op_in[218]
    DIRECTION INPUT ;
    USE SIGNAL ;
    SHAPE ABUTMENT ;
    PORT
      LAYER M4 ;
      RECT 789.234 410.304 789.426 410.328 ;
    END
  END op_in[218]
  PIN op_in[219]
    DIRECTION INPUT ;
    USE SIGNAL ;
    SHAPE ABUTMENT ;
    PORT
      LAYER M4 ;
      RECT 789.234 412.176 789.426 412.200 ;
    END
  END op_in[219]
  PIN op_in[220]
    DIRECTION INPUT ;
    USE SIGNAL ;
    SHAPE ABUTMENT ;
    PORT
      LAYER M4 ;
      RECT 789.234 414.048 789.426 414.072 ;
    END
  END op_in[220]
  PIN op_in[221]
    DIRECTION INPUT ;
    USE SIGNAL ;
    SHAPE ABUTMENT ;
    PORT
      LAYER M4 ;
      RECT 789.234 415.920 789.426 415.944 ;
    END
  END op_in[221]
  PIN op_in[222]
    DIRECTION INPUT ;
    USE SIGNAL ;
    SHAPE ABUTMENT ;
    PORT
      LAYER M4 ;
      RECT 789.234 417.792 789.426 417.816 ;
    END
  END op_in[222]
  PIN op_in[223]
    DIRECTION INPUT ;
    USE SIGNAL ;
    SHAPE ABUTMENT ;
    PORT
      LAYER M4 ;
      RECT 789.234 419.712 789.426 419.736 ;
    END
  END op_in[223]
  PIN op_in[224]
    DIRECTION INPUT ;
    USE SIGNAL ;
    SHAPE ABUTMENT ;
    PORT
      LAYER M4 ;
      RECT 789.234 421.584 789.426 421.608 ;
    END
  END op_in[224]
  PIN op_in[225]
    DIRECTION INPUT ;
    USE SIGNAL ;
    SHAPE ABUTMENT ;
    PORT
      LAYER M4 ;
      RECT 789.234 423.456 789.426 423.480 ;
    END
  END op_in[225]
  PIN op_in[226]
    DIRECTION INPUT ;
    USE SIGNAL ;
    SHAPE ABUTMENT ;
    PORT
      LAYER M4 ;
      RECT 789.234 425.328 789.426 425.352 ;
    END
  END op_in[226]
  PIN op_in[227]
    DIRECTION INPUT ;
    USE SIGNAL ;
    SHAPE ABUTMENT ;
    PORT
      LAYER M4 ;
      RECT 789.234 427.200 789.426 427.224 ;
    END
  END op_in[227]
  PIN op_in[228]
    DIRECTION INPUT ;
    USE SIGNAL ;
    SHAPE ABUTMENT ;
    PORT
      LAYER M4 ;
      RECT 789.234 429.072 789.426 429.096 ;
    END
  END op_in[228]
  PIN op_in[229]
    DIRECTION INPUT ;
    USE SIGNAL ;
    SHAPE ABUTMENT ;
    PORT
      LAYER M4 ;
      RECT 789.234 430.944 789.426 430.968 ;
    END
  END op_in[229]
  PIN op_in[230]
    DIRECTION INPUT ;
    USE SIGNAL ;
    SHAPE ABUTMENT ;
    PORT
      LAYER M4 ;
      RECT 789.234 432.864 789.426 432.888 ;
    END
  END op_in[230]
  PIN op_in[231]
    DIRECTION INPUT ;
    USE SIGNAL ;
    SHAPE ABUTMENT ;
    PORT
      LAYER M4 ;
      RECT 789.234 434.736 789.426 434.760 ;
    END
  END op_in[231]
  PIN op_in[232]
    DIRECTION INPUT ;
    USE SIGNAL ;
    SHAPE ABUTMENT ;
    PORT
      LAYER M4 ;
      RECT 789.234 436.608 789.426 436.632 ;
    END
  END op_in[232]
  PIN op_in[233]
    DIRECTION INPUT ;
    USE SIGNAL ;
    SHAPE ABUTMENT ;
    PORT
      LAYER M4 ;
      RECT 789.234 438.480 789.426 438.504 ;
    END
  END op_in[233]
  PIN op_in[234]
    DIRECTION INPUT ;
    USE SIGNAL ;
    SHAPE ABUTMENT ;
    PORT
      LAYER M4 ;
      RECT 789.234 440.352 789.426 440.376 ;
    END
  END op_in[234]
  PIN op_in[235]
    DIRECTION INPUT ;
    USE SIGNAL ;
    SHAPE ABUTMENT ;
    PORT
      LAYER M4 ;
      RECT 789.234 442.224 789.426 442.248 ;
    END
  END op_in[235]
  PIN op_in[236]
    DIRECTION INPUT ;
    USE SIGNAL ;
    SHAPE ABUTMENT ;
    PORT
      LAYER M4 ;
      RECT 789.234 444.144 789.426 444.168 ;
    END
  END op_in[236]
  PIN op_in[237]
    DIRECTION INPUT ;
    USE SIGNAL ;
    SHAPE ABUTMENT ;
    PORT
      LAYER M4 ;
      RECT 789.234 446.016 789.426 446.040 ;
    END
  END op_in[237]
  PIN op_in[238]
    DIRECTION INPUT ;
    USE SIGNAL ;
    SHAPE ABUTMENT ;
    PORT
      LAYER M4 ;
      RECT 789.234 447.888 789.426 447.912 ;
    END
  END op_in[238]
  PIN op_in[239]
    DIRECTION INPUT ;
    USE SIGNAL ;
    SHAPE ABUTMENT ;
    PORT
      LAYER M4 ;
      RECT 789.234 449.760 789.426 449.784 ;
    END
  END op_in[239]
  PIN op_in[240]
    DIRECTION INPUT ;
    USE SIGNAL ;
    SHAPE ABUTMENT ;
    PORT
      LAYER M4 ;
      RECT 789.234 451.632 789.426 451.656 ;
    END
  END op_in[240]
  PIN op_in[241]
    DIRECTION INPUT ;
    USE SIGNAL ;
    SHAPE ABUTMENT ;
    PORT
      LAYER M4 ;
      RECT 789.234 453.504 789.426 453.528 ;
    END
  END op_in[241]
  PIN op_in[242]
    DIRECTION INPUT ;
    USE SIGNAL ;
    SHAPE ABUTMENT ;
    PORT
      LAYER M4 ;
      RECT 789.234 455.424 789.426 455.448 ;
    END
  END op_in[242]
  PIN op_in[243]
    DIRECTION INPUT ;
    USE SIGNAL ;
    SHAPE ABUTMENT ;
    PORT
      LAYER M4 ;
      RECT 789.234 457.296 789.426 457.320 ;
    END
  END op_in[243]
  PIN op_in[244]
    DIRECTION INPUT ;
    USE SIGNAL ;
    SHAPE ABUTMENT ;
    PORT
      LAYER M4 ;
      RECT 789.234 459.168 789.426 459.192 ;
    END
  END op_in[244]
  PIN op_in[245]
    DIRECTION INPUT ;
    USE SIGNAL ;
    SHAPE ABUTMENT ;
    PORT
      LAYER M4 ;
      RECT 789.234 461.040 789.426 461.064 ;
    END
  END op_in[245]
  PIN op_in[246]
    DIRECTION INPUT ;
    USE SIGNAL ;
    SHAPE ABUTMENT ;
    PORT
      LAYER M4 ;
      RECT 789.234 462.912 789.426 462.936 ;
    END
  END op_in[246]
  PIN op_in[247]
    DIRECTION INPUT ;
    USE SIGNAL ;
    SHAPE ABUTMENT ;
    PORT
      LAYER M4 ;
      RECT 789.234 464.784 789.426 464.808 ;
    END
  END op_in[247]
  PIN op_in[248]
    DIRECTION INPUT ;
    USE SIGNAL ;
    SHAPE ABUTMENT ;
    PORT
      LAYER M4 ;
      RECT 789.234 466.704 789.426 466.728 ;
    END
  END op_in[248]
  PIN op_in[249]
    DIRECTION INPUT ;
    USE SIGNAL ;
    SHAPE ABUTMENT ;
    PORT
      LAYER M4 ;
      RECT 789.234 468.576 789.426 468.600 ;
    END
  END op_in[249]
  PIN op_in[250]
    DIRECTION INPUT ;
    USE SIGNAL ;
    SHAPE ABUTMENT ;
    PORT
      LAYER M4 ;
      RECT 789.234 470.448 789.426 470.472 ;
    END
  END op_in[250]
  PIN op_in[251]
    DIRECTION INPUT ;
    USE SIGNAL ;
    SHAPE ABUTMENT ;
    PORT
      LAYER M4 ;
      RECT 789.234 472.320 789.426 472.344 ;
    END
  END op_in[251]
  PIN op_in[252]
    DIRECTION INPUT ;
    USE SIGNAL ;
    SHAPE ABUTMENT ;
    PORT
      LAYER M4 ;
      RECT 789.234 474.192 789.426 474.216 ;
    END
  END op_in[252]
  PIN op_in[253]
    DIRECTION INPUT ;
    USE SIGNAL ;
    SHAPE ABUTMENT ;
    PORT
      LAYER M4 ;
      RECT 789.234 476.064 789.426 476.088 ;
    END
  END op_in[253]
  PIN op_in[254]
    DIRECTION INPUT ;
    USE SIGNAL ;
    SHAPE ABUTMENT ;
    PORT
      LAYER M4 ;
      RECT 789.234 477.984 789.426 478.008 ;
    END
  END op_in[254]
  PIN op_in[255]
    DIRECTION INPUT ;
    USE SIGNAL ;
    SHAPE ABUTMENT ;
    PORT
      LAYER M4 ;
      RECT 789.234 479.856 789.426 479.880 ;
    END
  END op_in[255]
  PIN op_in[256]
    DIRECTION INPUT ;
    USE SIGNAL ;
    SHAPE ABUTMENT ;
    PORT
      LAYER M4 ;
      RECT 789.234 481.728 789.426 481.752 ;
    END
  END op_in[256]
  PIN op_in[257]
    DIRECTION INPUT ;
    USE SIGNAL ;
    SHAPE ABUTMENT ;
    PORT
      LAYER M4 ;
      RECT 789.234 483.600 789.426 483.624 ;
    END
  END op_in[257]
  PIN op_in[258]
    DIRECTION INPUT ;
    USE SIGNAL ;
    SHAPE ABUTMENT ;
    PORT
      LAYER M4 ;
      RECT 789.234 485.472 789.426 485.496 ;
    END
  END op_in[258]
  PIN op_in[259]
    DIRECTION INPUT ;
    USE SIGNAL ;
    SHAPE ABUTMENT ;
    PORT
      LAYER M4 ;
      RECT 789.234 487.344 789.426 487.368 ;
    END
  END op_in[259]
  PIN op_in[260]
    DIRECTION INPUT ;
    USE SIGNAL ;
    SHAPE ABUTMENT ;
    PORT
      LAYER M4 ;
      RECT 789.234 489.264 789.426 489.288 ;
    END
  END op_in[260]
  PIN op_in[261]
    DIRECTION INPUT ;
    USE SIGNAL ;
    SHAPE ABUTMENT ;
    PORT
      LAYER M4 ;
      RECT 789.234 491.136 789.426 491.160 ;
    END
  END op_in[261]
  PIN op_in[262]
    DIRECTION INPUT ;
    USE SIGNAL ;
    SHAPE ABUTMENT ;
    PORT
      LAYER M4 ;
      RECT 789.234 493.008 789.426 493.032 ;
    END
  END op_in[262]
  PIN op_in[263]
    DIRECTION INPUT ;
    USE SIGNAL ;
    SHAPE ABUTMENT ;
    PORT
      LAYER M4 ;
      RECT 789.234 494.880 789.426 494.904 ;
    END
  END op_in[263]
  PIN op_in[264]
    DIRECTION INPUT ;
    USE SIGNAL ;
    SHAPE ABUTMENT ;
    PORT
      LAYER M4 ;
      RECT 789.234 496.752 789.426 496.776 ;
    END
  END op_in[264]
  PIN op_in[265]
    DIRECTION INPUT ;
    USE SIGNAL ;
    SHAPE ABUTMENT ;
    PORT
      LAYER M4 ;
      RECT 789.234 498.624 789.426 498.648 ;
    END
  END op_in[265]
  PIN op_in[266]
    DIRECTION INPUT ;
    USE SIGNAL ;
    SHAPE ABUTMENT ;
    PORT
      LAYER M4 ;
      RECT 789.234 500.496 789.426 500.520 ;
    END
  END op_in[266]
  PIN op_in[267]
    DIRECTION INPUT ;
    USE SIGNAL ;
    SHAPE ABUTMENT ;
    PORT
      LAYER M4 ;
      RECT 789.234 502.416 789.426 502.440 ;
    END
  END op_in[267]
  PIN op_in[268]
    DIRECTION INPUT ;
    USE SIGNAL ;
    SHAPE ABUTMENT ;
    PORT
      LAYER M4 ;
      RECT 789.234 504.288 789.426 504.312 ;
    END
  END op_in[268]
  PIN op_in[269]
    DIRECTION INPUT ;
    USE SIGNAL ;
    SHAPE ABUTMENT ;
    PORT
      LAYER M4 ;
      RECT 789.234 506.160 789.426 506.184 ;
    END
  END op_in[269]
  PIN op_in[270]
    DIRECTION INPUT ;
    USE SIGNAL ;
    SHAPE ABUTMENT ;
    PORT
      LAYER M4 ;
      RECT 789.234 508.032 789.426 508.056 ;
    END
  END op_in[270]
  PIN op_in[271]
    DIRECTION INPUT ;
    USE SIGNAL ;
    SHAPE ABUTMENT ;
    PORT
      LAYER M4 ;
      RECT 789.234 509.904 789.426 509.928 ;
    END
  END op_in[271]
  PIN op_in[272]
    DIRECTION INPUT ;
    USE SIGNAL ;
    SHAPE ABUTMENT ;
    PORT
      LAYER M4 ;
      RECT 789.234 511.776 789.426 511.800 ;
    END
  END op_in[272]
  PIN op_in[273]
    DIRECTION INPUT ;
    USE SIGNAL ;
    SHAPE ABUTMENT ;
    PORT
      LAYER M4 ;
      RECT 789.234 513.696 789.426 513.720 ;
    END
  END op_in[273]
  PIN op_in[274]
    DIRECTION INPUT ;
    USE SIGNAL ;
    SHAPE ABUTMENT ;
    PORT
      LAYER M4 ;
      RECT 789.234 515.568 789.426 515.592 ;
    END
  END op_in[274]
  PIN op_in[275]
    DIRECTION INPUT ;
    USE SIGNAL ;
    SHAPE ABUTMENT ;
    PORT
      LAYER M4 ;
      RECT 789.234 517.440 789.426 517.464 ;
    END
  END op_in[275]
  PIN op_in[276]
    DIRECTION INPUT ;
    USE SIGNAL ;
    SHAPE ABUTMENT ;
    PORT
      LAYER M4 ;
      RECT 789.234 519.312 789.426 519.336 ;
    END
  END op_in[276]
  PIN op_in[277]
    DIRECTION INPUT ;
    USE SIGNAL ;
    SHAPE ABUTMENT ;
    PORT
      LAYER M4 ;
      RECT 789.234 521.184 789.426 521.208 ;
    END
  END op_in[277]
  PIN op_in[278]
    DIRECTION INPUT ;
    USE SIGNAL ;
    SHAPE ABUTMENT ;
    PORT
      LAYER M4 ;
      RECT 789.234 523.056 789.426 523.080 ;
    END
  END op_in[278]
  PIN op_in[279]
    DIRECTION INPUT ;
    USE SIGNAL ;
    SHAPE ABUTMENT ;
    PORT
      LAYER M4 ;
      RECT 789.234 524.976 789.426 525.000 ;
    END
  END op_in[279]
  PIN op_in[280]
    DIRECTION INPUT ;
    USE SIGNAL ;
    SHAPE ABUTMENT ;
    PORT
      LAYER M4 ;
      RECT 789.234 526.848 789.426 526.872 ;
    END
  END op_in[280]
  PIN op_in[281]
    DIRECTION INPUT ;
    USE SIGNAL ;
    SHAPE ABUTMENT ;
    PORT
      LAYER M4 ;
      RECT 789.234 528.720 789.426 528.744 ;
    END
  END op_in[281]
  PIN op_in[282]
    DIRECTION INPUT ;
    USE SIGNAL ;
    SHAPE ABUTMENT ;
    PORT
      LAYER M4 ;
      RECT 789.234 530.592 789.426 530.616 ;
    END
  END op_in[282]
  PIN op_in[283]
    DIRECTION INPUT ;
    USE SIGNAL ;
    SHAPE ABUTMENT ;
    PORT
      LAYER M4 ;
      RECT 789.234 532.464 789.426 532.488 ;
    END
  END op_in[283]
  PIN op_in[284]
    DIRECTION INPUT ;
    USE SIGNAL ;
    SHAPE ABUTMENT ;
    PORT
      LAYER M4 ;
      RECT 789.234 534.336 789.426 534.360 ;
    END
  END op_in[284]
  PIN op_in[285]
    DIRECTION INPUT ;
    USE SIGNAL ;
    SHAPE ABUTMENT ;
    PORT
      LAYER M4 ;
      RECT 789.234 536.256 789.426 536.280 ;
    END
  END op_in[285]
  PIN op_in[286]
    DIRECTION INPUT ;
    USE SIGNAL ;
    SHAPE ABUTMENT ;
    PORT
      LAYER M4 ;
      RECT 789.234 538.128 789.426 538.152 ;
    END
  END op_in[286]
  PIN op_in[287]
    DIRECTION INPUT ;
    USE SIGNAL ;
    SHAPE ABUTMENT ;
    PORT
      LAYER M4 ;
      RECT 789.234 540.000 789.426 540.024 ;
    END
  END op_in[287]
  PIN op_in[288]
    DIRECTION INPUT ;
    USE SIGNAL ;
    SHAPE ABUTMENT ;
    PORT
      LAYER M4 ;
      RECT 789.234 541.872 789.426 541.896 ;
    END
  END op_in[288]
  PIN op_in[289]
    DIRECTION INPUT ;
    USE SIGNAL ;
    SHAPE ABUTMENT ;
    PORT
      LAYER M4 ;
      RECT 789.234 543.744 789.426 543.768 ;
    END
  END op_in[289]
  PIN op_in[290]
    DIRECTION INPUT ;
    USE SIGNAL ;
    SHAPE ABUTMENT ;
    PORT
      LAYER M4 ;
      RECT 789.234 545.616 789.426 545.640 ;
    END
  END op_in[290]
  PIN op_in[291]
    DIRECTION INPUT ;
    USE SIGNAL ;
    SHAPE ABUTMENT ;
    PORT
      LAYER M4 ;
      RECT 789.234 547.536 789.426 547.560 ;
    END
  END op_in[291]
  PIN op_in[292]
    DIRECTION INPUT ;
    USE SIGNAL ;
    SHAPE ABUTMENT ;
    PORT
      LAYER M4 ;
      RECT 789.234 549.408 789.426 549.432 ;
    END
  END op_in[292]
  PIN op_in[293]
    DIRECTION INPUT ;
    USE SIGNAL ;
    SHAPE ABUTMENT ;
    PORT
      LAYER M4 ;
      RECT 789.234 551.280 789.426 551.304 ;
    END
  END op_in[293]
  PIN op_in[294]
    DIRECTION INPUT ;
    USE SIGNAL ;
    SHAPE ABUTMENT ;
    PORT
      LAYER M4 ;
      RECT 789.234 553.152 789.426 553.176 ;
    END
  END op_in[294]
  PIN op_in[295]
    DIRECTION INPUT ;
    USE SIGNAL ;
    SHAPE ABUTMENT ;
    PORT
      LAYER M4 ;
      RECT 789.234 555.024 789.426 555.048 ;
    END
  END op_in[295]
  PIN op_in[296]
    DIRECTION INPUT ;
    USE SIGNAL ;
    SHAPE ABUTMENT ;
    PORT
      LAYER M4 ;
      RECT 789.234 556.896 789.426 556.920 ;
    END
  END op_in[296]
  PIN op_in[297]
    DIRECTION INPUT ;
    USE SIGNAL ;
    SHAPE ABUTMENT ;
    PORT
      LAYER M4 ;
      RECT 789.234 558.768 789.426 558.792 ;
    END
  END op_in[297]
  PIN op_in[298]
    DIRECTION INPUT ;
    USE SIGNAL ;
    SHAPE ABUTMENT ;
    PORT
      LAYER M4 ;
      RECT 789.234 560.688 789.426 560.712 ;
    END
  END op_in[298]
  PIN op_in[299]
    DIRECTION INPUT ;
    USE SIGNAL ;
    SHAPE ABUTMENT ;
    PORT
      LAYER M4 ;
      RECT 789.234 562.560 789.426 562.584 ;
    END
  END op_in[299]
  PIN op_in[300]
    DIRECTION INPUT ;
    USE SIGNAL ;
    SHAPE ABUTMENT ;
    PORT
      LAYER M4 ;
      RECT 789.234 564.432 789.426 564.456 ;
    END
  END op_in[300]
  PIN op_in[301]
    DIRECTION INPUT ;
    USE SIGNAL ;
    SHAPE ABUTMENT ;
    PORT
      LAYER M4 ;
      RECT 789.234 566.304 789.426 566.328 ;
    END
  END op_in[301]
  PIN op_in[302]
    DIRECTION INPUT ;
    USE SIGNAL ;
    SHAPE ABUTMENT ;
    PORT
      LAYER M4 ;
      RECT 789.234 568.176 789.426 568.200 ;
    END
  END op_in[302]
  PIN op_in[303]
    DIRECTION INPUT ;
    USE SIGNAL ;
    SHAPE ABUTMENT ;
    PORT
      LAYER M4 ;
      RECT 789.234 570.048 789.426 570.072 ;
    END
  END op_in[303]
  PIN op_in[304]
    DIRECTION INPUT ;
    USE SIGNAL ;
    SHAPE ABUTMENT ;
    PORT
      LAYER M4 ;
      RECT 789.234 571.968 789.426 571.992 ;
    END
  END op_in[304]
  PIN op_in[305]
    DIRECTION INPUT ;
    USE SIGNAL ;
    SHAPE ABUTMENT ;
    PORT
      LAYER M4 ;
      RECT 789.234 573.840 789.426 573.864 ;
    END
  END op_in[305]
  PIN op_in[306]
    DIRECTION INPUT ;
    USE SIGNAL ;
    SHAPE ABUTMENT ;
    PORT
      LAYER M4 ;
      RECT 789.234 575.712 789.426 575.736 ;
    END
  END op_in[306]
  PIN op_in[307]
    DIRECTION INPUT ;
    USE SIGNAL ;
    SHAPE ABUTMENT ;
    PORT
      LAYER M4 ;
      RECT 789.234 577.584 789.426 577.608 ;
    END
  END op_in[307]
  PIN op_in[308]
    DIRECTION INPUT ;
    USE SIGNAL ;
    SHAPE ABUTMENT ;
    PORT
      LAYER M4 ;
      RECT 789.234 579.456 789.426 579.480 ;
    END
  END op_in[308]
  PIN op_in[309]
    DIRECTION INPUT ;
    USE SIGNAL ;
    SHAPE ABUTMENT ;
    PORT
      LAYER M4 ;
      RECT 789.234 581.328 789.426 581.352 ;
    END
  END op_in[309]
  PIN op_in[310]
    DIRECTION INPUT ;
    USE SIGNAL ;
    SHAPE ABUTMENT ;
    PORT
      LAYER M4 ;
      RECT 789.234 583.248 789.426 583.272 ;
    END
  END op_in[310]
  PIN op_in[311]
    DIRECTION INPUT ;
    USE SIGNAL ;
    SHAPE ABUTMENT ;
    PORT
      LAYER M4 ;
      RECT 789.234 585.120 789.426 585.144 ;
    END
  END op_in[311]
  PIN op_in[312]
    DIRECTION INPUT ;
    USE SIGNAL ;
    SHAPE ABUTMENT ;
    PORT
      LAYER M4 ;
      RECT 789.234 586.992 789.426 587.016 ;
    END
  END op_in[312]
  PIN op_in[313]
    DIRECTION INPUT ;
    USE SIGNAL ;
    SHAPE ABUTMENT ;
    PORT
      LAYER M4 ;
      RECT 789.234 588.864 789.426 588.888 ;
    END
  END op_in[313]
  PIN op_in[314]
    DIRECTION INPUT ;
    USE SIGNAL ;
    SHAPE ABUTMENT ;
    PORT
      LAYER M4 ;
      RECT 789.234 590.736 789.426 590.760 ;
    END
  END op_in[314]
  PIN op_in[315]
    DIRECTION INPUT ;
    USE SIGNAL ;
    SHAPE ABUTMENT ;
    PORT
      LAYER M4 ;
      RECT 789.234 592.608 789.426 592.632 ;
    END
  END op_in[315]
  PIN op_in[316]
    DIRECTION INPUT ;
    USE SIGNAL ;
    SHAPE ABUTMENT ;
    PORT
      LAYER M4 ;
      RECT 789.234 594.528 789.426 594.552 ;
    END
  END op_in[316]
  PIN op_in[317]
    DIRECTION INPUT ;
    USE SIGNAL ;
    SHAPE ABUTMENT ;
    PORT
      LAYER M4 ;
      RECT 789.234 596.400 789.426 596.424 ;
    END
  END op_in[317]
  PIN op_in[318]
    DIRECTION INPUT ;
    USE SIGNAL ;
    SHAPE ABUTMENT ;
    PORT
      LAYER M4 ;
      RECT 789.234 598.272 789.426 598.296 ;
    END
  END op_in[318]
  PIN op_in[319]
    DIRECTION INPUT ;
    USE SIGNAL ;
    SHAPE ABUTMENT ;
    PORT
      LAYER M4 ;
      RECT 789.234 600.144 789.426 600.168 ;
    END
  END op_in[319]
  PIN op_in[320]
    DIRECTION INPUT ;
    USE SIGNAL ;
    SHAPE ABUTMENT ;
    PORT
      LAYER M4 ;
      RECT 789.234 602.016 789.426 602.040 ;
    END
  END op_in[320]
  PIN op_in[321]
    DIRECTION INPUT ;
    USE SIGNAL ;
    SHAPE ABUTMENT ;
    PORT
      LAYER M4 ;
      RECT 789.234 603.888 789.426 603.912 ;
    END
  END op_in[321]
  PIN op_in[322]
    DIRECTION INPUT ;
    USE SIGNAL ;
    SHAPE ABUTMENT ;
    PORT
      LAYER M4 ;
      RECT 789.234 605.808 789.426 605.832 ;
    END
  END op_in[322]
  PIN op_in[323]
    DIRECTION INPUT ;
    USE SIGNAL ;
    SHAPE ABUTMENT ;
    PORT
      LAYER M4 ;
      RECT 789.234 607.680 789.426 607.704 ;
    END
  END op_in[323]
  PIN op_in[324]
    DIRECTION INPUT ;
    USE SIGNAL ;
    SHAPE ABUTMENT ;
    PORT
      LAYER M4 ;
      RECT 789.234 609.552 789.426 609.576 ;
    END
  END op_in[324]
  PIN op_in[325]
    DIRECTION INPUT ;
    USE SIGNAL ;
    SHAPE ABUTMENT ;
    PORT
      LAYER M4 ;
      RECT 789.234 611.424 789.426 611.448 ;
    END
  END op_in[325]
  PIN op_in[326]
    DIRECTION INPUT ;
    USE SIGNAL ;
    SHAPE ABUTMENT ;
    PORT
      LAYER M4 ;
      RECT 789.234 613.296 789.426 613.320 ;
    END
  END op_in[326]
  PIN op_in[327]
    DIRECTION INPUT ;
    USE SIGNAL ;
    SHAPE ABUTMENT ;
    PORT
      LAYER M4 ;
      RECT 789.234 615.168 789.426 615.192 ;
    END
  END op_in[327]
  PIN op_in[328]
    DIRECTION INPUT ;
    USE SIGNAL ;
    SHAPE ABUTMENT ;
    PORT
      LAYER M4 ;
      RECT 789.234 617.040 789.426 617.064 ;
    END
  END op_in[328]
  PIN op_in[329]
    DIRECTION INPUT ;
    USE SIGNAL ;
    SHAPE ABUTMENT ;
    PORT
      LAYER M4 ;
      RECT 789.234 618.960 789.426 618.984 ;
    END
  END op_in[329]
  PIN op_in[330]
    DIRECTION INPUT ;
    USE SIGNAL ;
    SHAPE ABUTMENT ;
    PORT
      LAYER M4 ;
      RECT 789.234 620.832 789.426 620.856 ;
    END
  END op_in[330]
  PIN op_in[331]
    DIRECTION INPUT ;
    USE SIGNAL ;
    SHAPE ABUTMENT ;
    PORT
      LAYER M4 ;
      RECT 789.234 622.704 789.426 622.728 ;
    END
  END op_in[331]
  PIN op_in[332]
    DIRECTION INPUT ;
    USE SIGNAL ;
    SHAPE ABUTMENT ;
    PORT
      LAYER M4 ;
      RECT 789.234 624.576 789.426 624.600 ;
    END
  END op_in[332]
  PIN op_in[333]
    DIRECTION INPUT ;
    USE SIGNAL ;
    SHAPE ABUTMENT ;
    PORT
      LAYER M4 ;
      RECT 789.234 626.448 789.426 626.472 ;
    END
  END op_in[333]
  PIN op_in[334]
    DIRECTION INPUT ;
    USE SIGNAL ;
    SHAPE ABUTMENT ;
    PORT
      LAYER M4 ;
      RECT 789.234 628.320 789.426 628.344 ;
    END
  END op_in[334]
  PIN op_in[335]
    DIRECTION INPUT ;
    USE SIGNAL ;
    SHAPE ABUTMENT ;
    PORT
      LAYER M4 ;
      RECT 789.234 630.240 789.426 630.264 ;
    END
  END op_in[335]
  PIN op_in[336]
    DIRECTION INPUT ;
    USE SIGNAL ;
    SHAPE ABUTMENT ;
    PORT
      LAYER M4 ;
      RECT 789.234 632.112 789.426 632.136 ;
    END
  END op_in[336]
  PIN op_in[337]
    DIRECTION INPUT ;
    USE SIGNAL ;
    SHAPE ABUTMENT ;
    PORT
      LAYER M4 ;
      RECT 789.234 633.984 789.426 634.008 ;
    END
  END op_in[337]
  PIN op_in[338]
    DIRECTION INPUT ;
    USE SIGNAL ;
    SHAPE ABUTMENT ;
    PORT
      LAYER M4 ;
      RECT 789.234 635.856 789.426 635.880 ;
    END
  END op_in[338]
  PIN op_in[339]
    DIRECTION INPUT ;
    USE SIGNAL ;
    SHAPE ABUTMENT ;
    PORT
      LAYER M4 ;
      RECT 789.234 637.728 789.426 637.752 ;
    END
  END op_in[339]
  PIN op_in[340]
    DIRECTION INPUT ;
    USE SIGNAL ;
    SHAPE ABUTMENT ;
    PORT
      LAYER M4 ;
      RECT 789.234 639.600 789.426 639.624 ;
    END
  END op_in[340]
  PIN op_in[341]
    DIRECTION INPUT ;
    USE SIGNAL ;
    SHAPE ABUTMENT ;
    PORT
      LAYER M4 ;
      RECT 789.234 641.520 789.426 641.544 ;
    END
  END op_in[341]
  PIN op_in[342]
    DIRECTION INPUT ;
    USE SIGNAL ;
    SHAPE ABUTMENT ;
    PORT
      LAYER M4 ;
      RECT 789.234 643.392 789.426 643.416 ;
    END
  END op_in[342]
  PIN op_in[343]
    DIRECTION INPUT ;
    USE SIGNAL ;
    SHAPE ABUTMENT ;
    PORT
      LAYER M4 ;
      RECT 789.234 645.264 789.426 645.288 ;
    END
  END op_in[343]
  PIN op_in[344]
    DIRECTION INPUT ;
    USE SIGNAL ;
    SHAPE ABUTMENT ;
    PORT
      LAYER M4 ;
      RECT 789.234 647.136 789.426 647.160 ;
    END
  END op_in[344]
  PIN op_in[345]
    DIRECTION INPUT ;
    USE SIGNAL ;
    SHAPE ABUTMENT ;
    PORT
      LAYER M4 ;
      RECT 789.234 649.008 789.426 649.032 ;
    END
  END op_in[345]
  PIN op_in[346]
    DIRECTION INPUT ;
    USE SIGNAL ;
    SHAPE ABUTMENT ;
    PORT
      LAYER M4 ;
      RECT 789.234 650.880 789.426 650.904 ;
    END
  END op_in[346]
  PIN op_in[347]
    DIRECTION INPUT ;
    USE SIGNAL ;
    SHAPE ABUTMENT ;
    PORT
      LAYER M4 ;
      RECT 789.234 652.800 789.426 652.824 ;
    END
  END op_in[347]
  PIN op_in[348]
    DIRECTION INPUT ;
    USE SIGNAL ;
    SHAPE ABUTMENT ;
    PORT
      LAYER M4 ;
      RECT 789.234 654.672 789.426 654.696 ;
    END
  END op_in[348]
  PIN op_in[349]
    DIRECTION INPUT ;
    USE SIGNAL ;
    SHAPE ABUTMENT ;
    PORT
      LAYER M4 ;
      RECT 789.234 656.544 789.426 656.568 ;
    END
  END op_in[349]
  PIN op_in[350]
    DIRECTION INPUT ;
    USE SIGNAL ;
    SHAPE ABUTMENT ;
    PORT
      LAYER M4 ;
      RECT 789.234 658.416 789.426 658.440 ;
    END
  END op_in[350]
  PIN op_in[351]
    DIRECTION INPUT ;
    USE SIGNAL ;
    SHAPE ABUTMENT ;
    PORT
      LAYER M4 ;
      RECT 789.234 660.288 789.426 660.312 ;
    END
  END op_in[351]
  PIN op_in[352]
    DIRECTION INPUT ;
    USE SIGNAL ;
    SHAPE ABUTMENT ;
    PORT
      LAYER M4 ;
      RECT 789.234 662.160 789.426 662.184 ;
    END
  END op_in[352]
  PIN op_in[353]
    DIRECTION INPUT ;
    USE SIGNAL ;
    SHAPE ABUTMENT ;
    PORT
      LAYER M4 ;
      RECT 789.234 664.080 789.426 664.104 ;
    END
  END op_in[353]
  PIN op_in[354]
    DIRECTION INPUT ;
    USE SIGNAL ;
    SHAPE ABUTMENT ;
    PORT
      LAYER M4 ;
      RECT 789.234 665.952 789.426 665.976 ;
    END
  END op_in[354]
  PIN op_in[355]
    DIRECTION INPUT ;
    USE SIGNAL ;
    SHAPE ABUTMENT ;
    PORT
      LAYER M4 ;
      RECT 789.234 667.824 789.426 667.848 ;
    END
  END op_in[355]
  PIN op_in[356]
    DIRECTION INPUT ;
    USE SIGNAL ;
    SHAPE ABUTMENT ;
    PORT
      LAYER M4 ;
      RECT 789.234 669.696 789.426 669.720 ;
    END
  END op_in[356]
  PIN op_in[357]
    DIRECTION INPUT ;
    USE SIGNAL ;
    SHAPE ABUTMENT ;
    PORT
      LAYER M4 ;
      RECT 789.234 671.568 789.426 671.592 ;
    END
  END op_in[357]
  PIN op_in[358]
    DIRECTION INPUT ;
    USE SIGNAL ;
    SHAPE ABUTMENT ;
    PORT
      LAYER M4 ;
      RECT 789.234 673.440 789.426 673.464 ;
    END
  END op_in[358]
  PIN op_in[359]
    DIRECTION INPUT ;
    USE SIGNAL ;
    SHAPE ABUTMENT ;
    PORT
      LAYER M4 ;
      RECT 789.234 675.312 789.426 675.336 ;
    END
  END op_in[359]
  PIN op_in[360]
    DIRECTION INPUT ;
    USE SIGNAL ;
    SHAPE ABUTMENT ;
    PORT
      LAYER M4 ;
      RECT 789.234 677.232 789.426 677.256 ;
    END
  END op_in[360]
  PIN op_in[361]
    DIRECTION INPUT ;
    USE SIGNAL ;
    SHAPE ABUTMENT ;
    PORT
      LAYER M4 ;
      RECT 789.234 679.104 789.426 679.128 ;
    END
  END op_in[361]
  PIN op_in[362]
    DIRECTION INPUT ;
    USE SIGNAL ;
    SHAPE ABUTMENT ;
    PORT
      LAYER M4 ;
      RECT 789.234 680.976 789.426 681.000 ;
    END
  END op_in[362]
  PIN op_in[363]
    DIRECTION INPUT ;
    USE SIGNAL ;
    SHAPE ABUTMENT ;
    PORT
      LAYER M4 ;
      RECT 789.234 682.848 789.426 682.872 ;
    END
  END op_in[363]
  PIN op_in[364]
    DIRECTION INPUT ;
    USE SIGNAL ;
    SHAPE ABUTMENT ;
    PORT
      LAYER M4 ;
      RECT 789.234 684.720 789.426 684.744 ;
    END
  END op_in[364]
  PIN op_in[365]
    DIRECTION INPUT ;
    USE SIGNAL ;
    SHAPE ABUTMENT ;
    PORT
      LAYER M4 ;
      RECT 789.234 686.592 789.426 686.616 ;
    END
  END op_in[365]
  PIN op_in[366]
    DIRECTION INPUT ;
    USE SIGNAL ;
    SHAPE ABUTMENT ;
    PORT
      LAYER M4 ;
      RECT 789.234 688.512 789.426 688.536 ;
    END
  END op_in[366]
  PIN op_in[367]
    DIRECTION INPUT ;
    USE SIGNAL ;
    SHAPE ABUTMENT ;
    PORT
      LAYER M4 ;
      RECT 789.234 690.384 789.426 690.408 ;
    END
  END op_in[367]
  PIN op_in[368]
    DIRECTION INPUT ;
    USE SIGNAL ;
    SHAPE ABUTMENT ;
    PORT
      LAYER M4 ;
      RECT 789.234 692.256 789.426 692.280 ;
    END
  END op_in[368]
  PIN op_in[369]
    DIRECTION INPUT ;
    USE SIGNAL ;
    SHAPE ABUTMENT ;
    PORT
      LAYER M4 ;
      RECT 789.234 694.128 789.426 694.152 ;
    END
  END op_in[369]
  PIN op_in[370]
    DIRECTION INPUT ;
    USE SIGNAL ;
    SHAPE ABUTMENT ;
    PORT
      LAYER M4 ;
      RECT 789.234 696.000 789.426 696.024 ;
    END
  END op_in[370]
  PIN op_in[371]
    DIRECTION INPUT ;
    USE SIGNAL ;
    SHAPE ABUTMENT ;
    PORT
      LAYER M4 ;
      RECT 789.234 697.872 789.426 697.896 ;
    END
  END op_in[371]
  PIN op_in[372]
    DIRECTION INPUT ;
    USE SIGNAL ;
    SHAPE ABUTMENT ;
    PORT
      LAYER M4 ;
      RECT 789.234 699.792 789.426 699.816 ;
    END
  END op_in[372]
  PIN op_in[373]
    DIRECTION INPUT ;
    USE SIGNAL ;
    SHAPE ABUTMENT ;
    PORT
      LAYER M4 ;
      RECT 789.234 701.664 789.426 701.688 ;
    END
  END op_in[373]
  PIN op_in[374]
    DIRECTION INPUT ;
    USE SIGNAL ;
    SHAPE ABUTMENT ;
    PORT
      LAYER M4 ;
      RECT 789.234 703.536 789.426 703.560 ;
    END
  END op_in[374]
  PIN op_in[375]
    DIRECTION INPUT ;
    USE SIGNAL ;
    SHAPE ABUTMENT ;
    PORT
      LAYER M4 ;
      RECT 789.234 705.408 789.426 705.432 ;
    END
  END op_in[375]
  PIN op_in[376]
    DIRECTION INPUT ;
    USE SIGNAL ;
    SHAPE ABUTMENT ;
    PORT
      LAYER M4 ;
      RECT 789.234 707.280 789.426 707.304 ;
    END
  END op_in[376]
  PIN op_in[377]
    DIRECTION INPUT ;
    USE SIGNAL ;
    SHAPE ABUTMENT ;
    PORT
      LAYER M4 ;
      RECT 789.234 709.152 789.426 709.176 ;
    END
  END op_in[377]
  PIN op_in[378]
    DIRECTION INPUT ;
    USE SIGNAL ;
    SHAPE ABUTMENT ;
    PORT
      LAYER M4 ;
      RECT 789.234 711.072 789.426 711.096 ;
    END
  END op_in[378]
  PIN op_in[379]
    DIRECTION INPUT ;
    USE SIGNAL ;
    SHAPE ABUTMENT ;
    PORT
      LAYER M4 ;
      RECT 789.234 712.944 789.426 712.968 ;
    END
  END op_in[379]
  PIN res_out[0]
    DIRECTION OUTPUT ;
    USE SIGNAL ;
    SHAPE ABUTMENT ;
    PORT
      LAYER M4 ;
      RECT 789.234 714.816 789.426 714.840 ;
    END
  END res_out[0]
  PIN res_out[1]
    DIRECTION OUTPUT ;
    USE SIGNAL ;
    SHAPE ABUTMENT ;
    PORT
      LAYER M4 ;
      RECT 789.234 716.688 789.426 716.712 ;
    END
  END res_out[1]
  PIN res_out[2]
    DIRECTION OUTPUT ;
    USE SIGNAL ;
    SHAPE ABUTMENT ;
    PORT
      LAYER M4 ;
      RECT 789.234 718.560 789.426 718.584 ;
    END
  END res_out[2]
  PIN res_out[3]
    DIRECTION OUTPUT ;
    USE SIGNAL ;
    SHAPE ABUTMENT ;
    PORT
      LAYER M4 ;
      RECT 789.234 720.432 789.426 720.456 ;
    END
  END res_out[3]
  PIN res_out[4]
    DIRECTION OUTPUT ;
    USE SIGNAL ;
    SHAPE ABUTMENT ;
    PORT
      LAYER M4 ;
      RECT 789.234 722.352 789.426 722.376 ;
    END
  END res_out[4]
  PIN res_out[5]
    DIRECTION OUTPUT ;
    USE SIGNAL ;
    SHAPE ABUTMENT ;
    PORT
      LAYER M4 ;
      RECT 789.234 724.224 789.426 724.248 ;
    END
  END res_out[5]
  PIN res_out[6]
    DIRECTION OUTPUT ;
    USE SIGNAL ;
    SHAPE ABUTMENT ;
    PORT
      LAYER M4 ;
      RECT 789.234 726.096 789.426 726.120 ;
    END
  END res_out[6]
  PIN res_out[7]
    DIRECTION OUTPUT ;
    USE SIGNAL ;
    SHAPE ABUTMENT ;
    PORT
      LAYER M4 ;
      RECT 789.234 727.968 789.426 727.992 ;
    END
  END res_out[7]
  PIN res_out[8]
    DIRECTION OUTPUT ;
    USE SIGNAL ;
    SHAPE ABUTMENT ;
    PORT
      LAYER M4 ;
      RECT 789.234 729.840 789.426 729.864 ;
    END
  END res_out[8]
  PIN res_out[9]
    DIRECTION OUTPUT ;
    USE SIGNAL ;
    SHAPE ABUTMENT ;
    PORT
      LAYER M4 ;
      RECT 789.234 731.712 789.426 731.736 ;
    END
  END res_out[9]
  PIN res_out[10]
    DIRECTION OUTPUT ;
    USE SIGNAL ;
    SHAPE ABUTMENT ;
    PORT
      LAYER M4 ;
      RECT 789.234 733.632 789.426 733.656 ;
    END
  END res_out[10]
  PIN res_out[11]
    DIRECTION OUTPUT ;
    USE SIGNAL ;
    SHAPE ABUTMENT ;
    PORT
      LAYER M4 ;
      RECT 789.234 735.504 789.426 735.528 ;
    END
  END res_out[11]
  PIN res_out[12]
    DIRECTION OUTPUT ;
    USE SIGNAL ;
    SHAPE ABUTMENT ;
    PORT
      LAYER M4 ;
      RECT 789.234 737.376 789.426 737.400 ;
    END
  END res_out[12]
  PIN res_out[13]
    DIRECTION OUTPUT ;
    USE SIGNAL ;
    SHAPE ABUTMENT ;
    PORT
      LAYER M4 ;
      RECT 789.234 739.248 789.426 739.272 ;
    END
  END res_out[13]
  PIN res_out[14]
    DIRECTION OUTPUT ;
    USE SIGNAL ;
    SHAPE ABUTMENT ;
    PORT
      LAYER M4 ;
      RECT 789.234 741.120 789.426 741.144 ;
    END
  END res_out[14]
  PIN res_out[15]
    DIRECTION OUTPUT ;
    USE SIGNAL ;
    SHAPE ABUTMENT ;
    PORT
      LAYER M4 ;
      RECT 789.234 742.992 789.426 743.016 ;
    END
  END res_out[15]
  PIN res_out[16]
    DIRECTION OUTPUT ;
    USE SIGNAL ;
    SHAPE ABUTMENT ;
    PORT
      LAYER M4 ;
      RECT 789.234 744.864 789.426 744.888 ;
    END
  END res_out[16]
  PIN res_out[17]
    DIRECTION OUTPUT ;
    USE SIGNAL ;
    SHAPE ABUTMENT ;
    PORT
      LAYER M4 ;
      RECT 789.234 746.784 789.426 746.808 ;
    END
  END res_out[17]
  PIN res_out[18]
    DIRECTION OUTPUT ;
    USE SIGNAL ;
    SHAPE ABUTMENT ;
    PORT
      LAYER M4 ;
      RECT 789.234 748.656 789.426 748.680 ;
    END
  END res_out[18]
  PIN res_out[19]
    DIRECTION OUTPUT ;
    USE SIGNAL ;
    SHAPE ABUTMENT ;
    PORT
      LAYER M4 ;
      RECT 789.234 750.528 789.426 750.552 ;
    END
  END res_out[19]
  PIN res_out[20]
    DIRECTION OUTPUT ;
    USE SIGNAL ;
    SHAPE ABUTMENT ;
    PORT
      LAYER M4 ;
      RECT 789.234 752.400 789.426 752.424 ;
    END
  END res_out[20]
  PIN res_out[21]
    DIRECTION OUTPUT ;
    USE SIGNAL ;
    SHAPE ABUTMENT ;
    PORT
      LAYER M4 ;
      RECT 789.234 754.272 789.426 754.296 ;
    END
  END res_out[21]
  PIN res_out[22]
    DIRECTION OUTPUT ;
    USE SIGNAL ;
    SHAPE ABUTMENT ;
    PORT
      LAYER M4 ;
      RECT 789.234 756.144 789.426 756.168 ;
    END
  END res_out[22]
  PIN res_out[23]
    DIRECTION OUTPUT ;
    USE SIGNAL ;
    SHAPE ABUTMENT ;
    PORT
      LAYER M4 ;
      RECT 789.234 758.064 789.426 758.088 ;
    END
  END res_out[23]
  PIN res_out[24]
    DIRECTION OUTPUT ;
    USE SIGNAL ;
    SHAPE ABUTMENT ;
    PORT
      LAYER M4 ;
      RECT 789.234 759.936 789.426 759.960 ;
    END
  END res_out[24]
  PIN res_out[25]
    DIRECTION OUTPUT ;
    USE SIGNAL ;
    SHAPE ABUTMENT ;
    PORT
      LAYER M4 ;
      RECT 789.234 761.808 789.426 761.832 ;
    END
  END res_out[25]
  PIN res_out[26]
    DIRECTION OUTPUT ;
    USE SIGNAL ;
    SHAPE ABUTMENT ;
    PORT
      LAYER M4 ;
      RECT 789.234 763.680 789.426 763.704 ;
    END
  END res_out[26]
  PIN res_out[27]
    DIRECTION OUTPUT ;
    USE SIGNAL ;
    SHAPE ABUTMENT ;
    PORT
      LAYER M4 ;
      RECT 789.234 765.552 789.426 765.576 ;
    END
  END res_out[27]
  PIN res_out[28]
    DIRECTION OUTPUT ;
    USE SIGNAL ;
    SHAPE ABUTMENT ;
    PORT
      LAYER M4 ;
      RECT 789.234 767.424 789.426 767.448 ;
    END
  END res_out[28]
  PIN res_out[29]
    DIRECTION OUTPUT ;
    USE SIGNAL ;
    SHAPE ABUTMENT ;
    PORT
      LAYER M4 ;
      RECT 789.234 769.344 789.426 769.368 ;
    END
  END res_out[29]
  PIN res_out[30]
    DIRECTION OUTPUT ;
    USE SIGNAL ;
    SHAPE ABUTMENT ;
    PORT
      LAYER M4 ;
      RECT 789.234 771.216 789.426 771.240 ;
    END
  END res_out[30]
  PIN res_out[31]
    DIRECTION OUTPUT ;
    USE SIGNAL ;
    SHAPE ABUTMENT ;
    PORT
      LAYER M4 ;
      RECT 789.234 773.088 789.426 773.112 ;
    END
  END res_out[31]
  PIN res_out[32]
    DIRECTION OUTPUT ;
    USE SIGNAL ;
    SHAPE ABUTMENT ;
    PORT
      LAYER M4 ;
      RECT 789.234 774.960 789.426 774.984 ;
    END
  END res_out[32]
  PIN res_out[33]
    DIRECTION OUTPUT ;
    USE SIGNAL ;
    SHAPE ABUTMENT ;
    PORT
      LAYER M4 ;
      RECT 789.234 776.832 789.426 776.856 ;
    END
  END res_out[33]
  PIN res_out[34]
    DIRECTION OUTPUT ;
    USE SIGNAL ;
    SHAPE ABUTMENT ;
    PORT
      LAYER M4 ;
      RECT 789.234 778.704 789.426 778.728 ;
    END
  END res_out[34]
  PIN res_out[35]
    DIRECTION OUTPUT ;
    USE SIGNAL ;
    SHAPE ABUTMENT ;
    PORT
      LAYER M4 ;
      RECT 789.234 780.624 789.426 780.648 ;
    END
  END res_out[35]
  PIN res_out[36]
    DIRECTION OUTPUT ;
    USE SIGNAL ;
    SHAPE ABUTMENT ;
    PORT
      LAYER M4 ;
      RECT 789.234 782.496 789.426 782.520 ;
    END
  END res_out[36]
  PIN res_out[37]
    DIRECTION OUTPUT ;
    USE SIGNAL ;
    SHAPE ABUTMENT ;
    PORT
      LAYER M4 ;
      RECT 789.234 784.368 789.426 784.392 ;
    END
  END res_out[37]
  PIN res_out[38]
    DIRECTION OUTPUT ;
    USE SIGNAL ;
    SHAPE ABUTMENT ;
    PORT
      LAYER M4 ;
      RECT 789.234 786.240 789.426 786.264 ;
    END
  END res_out[38]
  PIN res_out[39]
    DIRECTION OUTPUT ;
    USE SIGNAL ;
    SHAPE ABUTMENT ;
    PORT
      LAYER M4 ;
      RECT 789.234 788.112 789.426 788.136 ;
    END
  END res_out[39]
  PIN res_out[40]
    DIRECTION OUTPUT ;
    USE SIGNAL ;
    SHAPE ABUTMENT ;
    PORT
      LAYER M4 ;
      RECT 789.234 789.984 789.426 790.008 ;
    END
  END res_out[40]
  PIN res_out[41]
    DIRECTION OUTPUT ;
    USE SIGNAL ;
    SHAPE ABUTMENT ;
    PORT
      LAYER M4 ;
      RECT 789.234 791.904 789.426 791.928 ;
    END
  END res_out[41]
  PIN res_out[42]
    DIRECTION OUTPUT ;
    USE SIGNAL ;
    SHAPE ABUTMENT ;
    PORT
      LAYER M4 ;
      RECT 789.234 793.776 789.426 793.800 ;
    END
  END res_out[42]
  PIN res_out[43]
    DIRECTION OUTPUT ;
    USE SIGNAL ;
    SHAPE ABUTMENT ;
    PORT
      LAYER M4 ;
      RECT 789.234 795.648 789.426 795.672 ;
    END
  END res_out[43]
  PIN res_out[44]
    DIRECTION OUTPUT ;
    USE SIGNAL ;
    SHAPE ABUTMENT ;
    PORT
      LAYER M4 ;
      RECT 789.234 797.520 789.426 797.544 ;
    END
  END res_out[44]
  PIN res_out[45]
    DIRECTION OUTPUT ;
    USE SIGNAL ;
    SHAPE ABUTMENT ;
    PORT
      LAYER M4 ;
      RECT 789.234 799.392 789.426 799.416 ;
    END
  END res_out[45]
  PIN res_out[46]
    DIRECTION OUTPUT ;
    USE SIGNAL ;
    SHAPE ABUTMENT ;
    PORT
      LAYER M4 ;
      RECT 789.234 801.264 789.426 801.288 ;
    END
  END res_out[46]
  PIN res_out[47]
    DIRECTION OUTPUT ;
    USE SIGNAL ;
    SHAPE ABUTMENT ;
    PORT
      LAYER M4 ;
      RECT 789.234 803.136 789.426 803.160 ;
    END
  END res_out[47]
  PIN res_out[48]
    DIRECTION OUTPUT ;
    USE SIGNAL ;
    SHAPE ABUTMENT ;
    PORT
      LAYER M4 ;
      RECT 789.234 805.056 789.426 805.080 ;
    END
  END res_out[48]
  PIN res_out[49]
    DIRECTION OUTPUT ;
    USE SIGNAL ;
    SHAPE ABUTMENT ;
    PORT
      LAYER M4 ;
      RECT 789.234 806.928 789.426 806.952 ;
    END
  END res_out[49]
  PIN res_out[50]
    DIRECTION OUTPUT ;
    USE SIGNAL ;
    SHAPE ABUTMENT ;
    PORT
      LAYER M4 ;
      RECT 789.234 808.800 789.426 808.824 ;
    END
  END res_out[50]
  PIN res_out[51]
    DIRECTION OUTPUT ;
    USE SIGNAL ;
    SHAPE ABUTMENT ;
    PORT
      LAYER M4 ;
      RECT 789.234 810.672 789.426 810.696 ;
    END
  END res_out[51]
  PIN res_out[52]
    DIRECTION OUTPUT ;
    USE SIGNAL ;
    SHAPE ABUTMENT ;
    PORT
      LAYER M4 ;
      RECT 789.234 812.544 789.426 812.568 ;
    END
  END res_out[52]
  PIN res_out[53]
    DIRECTION OUTPUT ;
    USE SIGNAL ;
    SHAPE ABUTMENT ;
    PORT
      LAYER M4 ;
      RECT 789.234 814.416 789.426 814.440 ;
    END
  END res_out[53]
  PIN res_out[54]
    DIRECTION OUTPUT ;
    USE SIGNAL ;
    SHAPE ABUTMENT ;
    PORT
      LAYER M4 ;
      RECT 789.234 816.336 789.426 816.360 ;
    END
  END res_out[54]
  PIN res_out[55]
    DIRECTION OUTPUT ;
    USE SIGNAL ;
    SHAPE ABUTMENT ;
    PORT
      LAYER M4 ;
      RECT 789.234 818.208 789.426 818.232 ;
    END
  END res_out[55]
  PIN res_out[56]
    DIRECTION OUTPUT ;
    USE SIGNAL ;
    SHAPE ABUTMENT ;
    PORT
      LAYER M4 ;
      RECT 789.234 820.080 789.426 820.104 ;
    END
  END res_out[56]
  PIN res_out[57]
    DIRECTION OUTPUT ;
    USE SIGNAL ;
    SHAPE ABUTMENT ;
    PORT
      LAYER M4 ;
      RECT 789.234 821.952 789.426 821.976 ;
    END
  END res_out[57]
  PIN res_out[58]
    DIRECTION OUTPUT ;
    USE SIGNAL ;
    SHAPE ABUTMENT ;
    PORT
      LAYER M4 ;
      RECT 789.234 823.824 789.426 823.848 ;
    END
  END res_out[58]
  PIN res_out[59]
    DIRECTION OUTPUT ;
    USE SIGNAL ;
    SHAPE ABUTMENT ;
    PORT
      LAYER M4 ;
      RECT 789.234 825.696 789.426 825.720 ;
    END
  END res_out[59]
  PIN res_out[60]
    DIRECTION OUTPUT ;
    USE SIGNAL ;
    SHAPE ABUTMENT ;
    PORT
      LAYER M4 ;
      RECT 789.234 827.616 789.426 827.640 ;
    END
  END res_out[60]
  PIN res_out[61]
    DIRECTION OUTPUT ;
    USE SIGNAL ;
    SHAPE ABUTMENT ;
    PORT
      LAYER M4 ;
      RECT 789.234 829.488 789.426 829.512 ;
    END
  END res_out[61]
  PIN res_out[62]
    DIRECTION OUTPUT ;
    USE SIGNAL ;
    SHAPE ABUTMENT ;
    PORT
      LAYER M4 ;
      RECT 789.234 831.360 789.426 831.384 ;
    END
  END res_out[62]
  PIN res_out[63]
    DIRECTION OUTPUT ;
    USE SIGNAL ;
    SHAPE ABUTMENT ;
    PORT
      LAYER M4 ;
      RECT 789.234 833.232 789.426 833.256 ;
    END
  END res_out[63]
  PIN res_out[64]
    DIRECTION OUTPUT ;
    USE SIGNAL ;
    SHAPE ABUTMENT ;
    PORT
      LAYER M4 ;
      RECT 789.234 835.104 789.426 835.128 ;
    END
  END res_out[64]
  PIN res_out[65]
    DIRECTION OUTPUT ;
    USE SIGNAL ;
    SHAPE ABUTMENT ;
    PORT
      LAYER M4 ;
      RECT 789.234 836.976 789.426 837.000 ;
    END
  END res_out[65]
  PIN res_out[66]
    DIRECTION OUTPUT ;
    USE SIGNAL ;
    SHAPE ABUTMENT ;
    PORT
      LAYER M4 ;
      RECT 789.234 838.896 789.426 838.920 ;
    END
  END res_out[66]
  PIN res_out[67]
    DIRECTION OUTPUT ;
    USE SIGNAL ;
    SHAPE ABUTMENT ;
    PORT
      LAYER M4 ;
      RECT 789.234 840.768 789.426 840.792 ;
    END
  END res_out[67]
  PIN res_out[68]
    DIRECTION OUTPUT ;
    USE SIGNAL ;
    SHAPE ABUTMENT ;
    PORT
      LAYER M4 ;
      RECT 789.234 842.640 789.426 842.664 ;
    END
  END res_out[68]
  PIN res_out[69]
    DIRECTION OUTPUT ;
    USE SIGNAL ;
    SHAPE ABUTMENT ;
    PORT
      LAYER M4 ;
      RECT 789.234 844.512 789.426 844.536 ;
    END
  END res_out[69]
  PIN res_out[70]
    DIRECTION OUTPUT ;
    USE SIGNAL ;
    SHAPE ABUTMENT ;
    PORT
      LAYER M4 ;
      RECT 789.234 846.384 789.426 846.408 ;
    END
  END res_out[70]
  PIN res_out[71]
    DIRECTION OUTPUT ;
    USE SIGNAL ;
    SHAPE ABUTMENT ;
    PORT
      LAYER M4 ;
      RECT 789.234 848.256 789.426 848.280 ;
    END
  END res_out[71]
  PIN res_out[72]
    DIRECTION OUTPUT ;
    USE SIGNAL ;
    SHAPE ABUTMENT ;
    PORT
      LAYER M4 ;
      RECT 789.234 850.176 789.426 850.200 ;
    END
  END res_out[72]
  PIN res_out[73]
    DIRECTION OUTPUT ;
    USE SIGNAL ;
    SHAPE ABUTMENT ;
    PORT
      LAYER M4 ;
      RECT 789.234 852.048 789.426 852.072 ;
    END
  END res_out[73]
  PIN res_out[74]
    DIRECTION OUTPUT ;
    USE SIGNAL ;
    SHAPE ABUTMENT ;
    PORT
      LAYER M4 ;
      RECT 789.234 853.920 789.426 853.944 ;
    END
  END res_out[74]
  PIN res_out[75]
    DIRECTION OUTPUT ;
    USE SIGNAL ;
    SHAPE ABUTMENT ;
    PORT
      LAYER M4 ;
      RECT 789.234 855.792 789.426 855.816 ;
    END
  END res_out[75]
  PIN res_out[76]
    DIRECTION OUTPUT ;
    USE SIGNAL ;
    SHAPE ABUTMENT ;
    PORT
      LAYER M4 ;
      RECT 789.234 857.664 789.426 857.688 ;
    END
  END res_out[76]
  PIN res_out[77]
    DIRECTION OUTPUT ;
    USE SIGNAL ;
    SHAPE ABUTMENT ;
    PORT
      LAYER M4 ;
      RECT 789.234 859.536 789.426 859.560 ;
    END
  END res_out[77]
  PIN res_out[78]
    DIRECTION OUTPUT ;
    USE SIGNAL ;
    SHAPE ABUTMENT ;
    PORT
      LAYER M4 ;
      RECT 789.234 861.408 789.426 861.432 ;
    END
  END res_out[78]
  PIN res_out[79]
    DIRECTION OUTPUT ;
    USE SIGNAL ;
    SHAPE ABUTMENT ;
    PORT
      LAYER M4 ;
      RECT 789.234 863.328 789.426 863.352 ;
    END
  END res_out[79]
  PIN res_out[80]
    DIRECTION OUTPUT ;
    USE SIGNAL ;
    SHAPE ABUTMENT ;
    PORT
      LAYER M4 ;
      RECT 789.234 865.200 789.426 865.224 ;
    END
  END res_out[80]
  PIN res_out[81]
    DIRECTION OUTPUT ;
    USE SIGNAL ;
    SHAPE ABUTMENT ;
    PORT
      LAYER M4 ;
      RECT 789.234 867.072 789.426 867.096 ;
    END
  END res_out[81]
  PIN res_out[82]
    DIRECTION OUTPUT ;
    USE SIGNAL ;
    SHAPE ABUTMENT ;
    PORT
      LAYER M4 ;
      RECT 789.234 868.944 789.426 868.968 ;
    END
  END res_out[82]
  PIN res_out[83]
    DIRECTION OUTPUT ;
    USE SIGNAL ;
    SHAPE ABUTMENT ;
    PORT
      LAYER M4 ;
      RECT 789.234 870.816 789.426 870.840 ;
    END
  END res_out[83]
  PIN res_out[84]
    DIRECTION OUTPUT ;
    USE SIGNAL ;
    SHAPE ABUTMENT ;
    PORT
      LAYER M4 ;
      RECT 789.234 872.688 789.426 872.712 ;
    END
  END res_out[84]
  PIN res_out[85]
    DIRECTION OUTPUT ;
    USE SIGNAL ;
    SHAPE ABUTMENT ;
    PORT
      LAYER M4 ;
      RECT 789.234 874.608 789.426 874.632 ;
    END
  END res_out[85]
  PIN res_out[86]
    DIRECTION OUTPUT ;
    USE SIGNAL ;
    SHAPE ABUTMENT ;
    PORT
      LAYER M4 ;
      RECT 789.234 876.480 789.426 876.504 ;
    END
  END res_out[86]
  PIN res_out[87]
    DIRECTION OUTPUT ;
    USE SIGNAL ;
    SHAPE ABUTMENT ;
    PORT
      LAYER M4 ;
      RECT 789.234 878.352 789.426 878.376 ;
    END
  END res_out[87]
  PIN res_out[88]
    DIRECTION OUTPUT ;
    USE SIGNAL ;
    SHAPE ABUTMENT ;
    PORT
      LAYER M4 ;
      RECT 789.234 880.224 789.426 880.248 ;
    END
  END res_out[88]
  PIN res_out[89]
    DIRECTION OUTPUT ;
    USE SIGNAL ;
    SHAPE ABUTMENT ;
    PORT
      LAYER M4 ;
      RECT 789.234 882.096 789.426 882.120 ;
    END
  END res_out[89]
  PIN res_out[90]
    DIRECTION OUTPUT ;
    USE SIGNAL ;
    SHAPE ABUTMENT ;
    PORT
      LAYER M4 ;
      RECT 789.234 883.968 789.426 883.992 ;
    END
  END res_out[90]
  PIN res_out[91]
    DIRECTION OUTPUT ;
    USE SIGNAL ;
    SHAPE ABUTMENT ;
    PORT
      LAYER M4 ;
      RECT 789.234 885.888 789.426 885.912 ;
    END
  END res_out[91]
  PIN res_out[92]
    DIRECTION OUTPUT ;
    USE SIGNAL ;
    SHAPE ABUTMENT ;
    PORT
      LAYER M4 ;
      RECT 789.234 887.760 789.426 887.784 ;
    END
  END res_out[92]
  PIN res_out[93]
    DIRECTION OUTPUT ;
    USE SIGNAL ;
    SHAPE ABUTMENT ;
    PORT
      LAYER M4 ;
      RECT 789.234 889.632 789.426 889.656 ;
    END
  END res_out[93]
  PIN res_out[94]
    DIRECTION OUTPUT ;
    USE SIGNAL ;
    SHAPE ABUTMENT ;
    PORT
      LAYER M4 ;
      RECT 789.234 891.504 789.426 891.528 ;
    END
  END res_out[94]
  PIN res_out[95]
    DIRECTION OUTPUT ;
    USE SIGNAL ;
    SHAPE ABUTMENT ;
    PORT
      LAYER M4 ;
      RECT 789.234 893.376 789.426 893.400 ;
    END
  END res_out[95]
  PIN res_out[96]
    DIRECTION OUTPUT ;
    USE SIGNAL ;
    SHAPE ABUTMENT ;
    PORT
      LAYER M4 ;
      RECT 789.234 895.248 789.426 895.272 ;
    END
  END res_out[96]
  PIN res_out[97]
    DIRECTION OUTPUT ;
    USE SIGNAL ;
    SHAPE ABUTMENT ;
    PORT
      LAYER M4 ;
      RECT 789.234 897.168 789.426 897.192 ;
    END
  END res_out[97]
  PIN res_out[98]
    DIRECTION OUTPUT ;
    USE SIGNAL ;
    SHAPE ABUTMENT ;
    PORT
      LAYER M4 ;
      RECT 789.234 899.040 789.426 899.064 ;
    END
  END res_out[98]
  PIN res_out[99]
    DIRECTION OUTPUT ;
    USE SIGNAL ;
    SHAPE ABUTMENT ;
    PORT
      LAYER M4 ;
      RECT 789.234 900.912 789.426 900.936 ;
    END
  END res_out[99]
  PIN res_out[100]
    DIRECTION OUTPUT ;
    USE SIGNAL ;
    SHAPE ABUTMENT ;
    PORT
      LAYER M4 ;
      RECT 789.234 902.784 789.426 902.808 ;
    END
  END res_out[100]
  PIN res_out[101]
    DIRECTION OUTPUT ;
    USE SIGNAL ;
    SHAPE ABUTMENT ;
    PORT
      LAYER M4 ;
      RECT 789.234 904.656 789.426 904.680 ;
    END
  END res_out[101]
  PIN res_out[102]
    DIRECTION OUTPUT ;
    USE SIGNAL ;
    SHAPE ABUTMENT ;
    PORT
      LAYER M4 ;
      RECT 789.234 906.528 789.426 906.552 ;
    END
  END res_out[102]
  PIN res_out[103]
    DIRECTION OUTPUT ;
    USE SIGNAL ;
    SHAPE ABUTMENT ;
    PORT
      LAYER M4 ;
      RECT 789.234 908.448 789.426 908.472 ;
    END
  END res_out[103]
  PIN res_out[104]
    DIRECTION OUTPUT ;
    USE SIGNAL ;
    SHAPE ABUTMENT ;
    PORT
      LAYER M4 ;
      RECT 789.234 910.320 789.426 910.344 ;
    END
  END res_out[104]
  PIN res_out[105]
    DIRECTION OUTPUT ;
    USE SIGNAL ;
    SHAPE ABUTMENT ;
    PORT
      LAYER M4 ;
      RECT 789.234 912.192 789.426 912.216 ;
    END
  END res_out[105]
  PIN res_out[106]
    DIRECTION OUTPUT ;
    USE SIGNAL ;
    SHAPE ABUTMENT ;
    PORT
      LAYER M4 ;
      RECT 789.234 914.064 789.426 914.088 ;
    END
  END res_out[106]
  PIN res_out[107]
    DIRECTION OUTPUT ;
    USE SIGNAL ;
    SHAPE ABUTMENT ;
    PORT
      LAYER M4 ;
      RECT 789.234 915.936 789.426 915.960 ;
    END
  END res_out[107]
  PIN res_out[108]
    DIRECTION OUTPUT ;
    USE SIGNAL ;
    SHAPE ABUTMENT ;
    PORT
      LAYER M4 ;
      RECT 789.234 917.808 789.426 917.832 ;
    END
  END res_out[108]
  PIN res_out[109]
    DIRECTION OUTPUT ;
    USE SIGNAL ;
    SHAPE ABUTMENT ;
    PORT
      LAYER M4 ;
      RECT 789.234 919.680 789.426 919.704 ;
    END
  END res_out[109]
  PIN res_out[110]
    DIRECTION OUTPUT ;
    USE SIGNAL ;
    SHAPE ABUTMENT ;
    PORT
      LAYER M4 ;
      RECT 789.234 921.600 789.426 921.624 ;
    END
  END res_out[110]
  PIN res_out[111]
    DIRECTION OUTPUT ;
    USE SIGNAL ;
    SHAPE ABUTMENT ;
    PORT
      LAYER M4 ;
      RECT 789.234 923.472 789.426 923.496 ;
    END
  END res_out[111]
  PIN res_out[112]
    DIRECTION OUTPUT ;
    USE SIGNAL ;
    SHAPE ABUTMENT ;
    PORT
      LAYER M4 ;
      RECT 789.234 925.344 789.426 925.368 ;
    END
  END res_out[112]
  PIN res_out[113]
    DIRECTION OUTPUT ;
    USE SIGNAL ;
    SHAPE ABUTMENT ;
    PORT
      LAYER M4 ;
      RECT 789.234 927.216 789.426 927.240 ;
    END
  END res_out[113]
  PIN res_out[114]
    DIRECTION OUTPUT ;
    USE SIGNAL ;
    SHAPE ABUTMENT ;
    PORT
      LAYER M4 ;
      RECT 789.234 929.088 789.426 929.112 ;
    END
  END res_out[114]
  PIN res_out[115]
    DIRECTION OUTPUT ;
    USE SIGNAL ;
    SHAPE ABUTMENT ;
    PORT
      LAYER M4 ;
      RECT 789.234 930.960 789.426 930.984 ;
    END
  END res_out[115]
  PIN res_out[116]
    DIRECTION OUTPUT ;
    USE SIGNAL ;
    SHAPE ABUTMENT ;
    PORT
      LAYER M4 ;
      RECT 789.234 932.880 789.426 932.904 ;
    END
  END res_out[116]
  PIN res_out[117]
    DIRECTION OUTPUT ;
    USE SIGNAL ;
    SHAPE ABUTMENT ;
    PORT
      LAYER M4 ;
      RECT 789.234 934.752 789.426 934.776 ;
    END
  END res_out[117]
  PIN res_out[118]
    DIRECTION OUTPUT ;
    USE SIGNAL ;
    SHAPE ABUTMENT ;
    PORT
      LAYER M4 ;
      RECT 789.234 936.624 789.426 936.648 ;
    END
  END res_out[118]
  PIN res_out[119]
    DIRECTION OUTPUT ;
    USE SIGNAL ;
    SHAPE ABUTMENT ;
    PORT
      LAYER M4 ;
      RECT 789.234 938.496 789.426 938.520 ;
    END
  END res_out[119]
  PIN res_out[120]
    DIRECTION OUTPUT ;
    USE SIGNAL ;
    SHAPE ABUTMENT ;
    PORT
      LAYER M4 ;
      RECT 789.234 940.368 789.426 940.392 ;
    END
  END res_out[120]
  PIN res_out[121]
    DIRECTION OUTPUT ;
    USE SIGNAL ;
    SHAPE ABUTMENT ;
    PORT
      LAYER M4 ;
      RECT 789.234 942.240 789.426 942.264 ;
    END
  END res_out[121]
  PIN res_out[122]
    DIRECTION OUTPUT ;
    USE SIGNAL ;
    SHAPE ABUTMENT ;
    PORT
      LAYER M4 ;
      RECT 789.234 944.160 789.426 944.184 ;
    END
  END res_out[122]
  PIN res_out[123]
    DIRECTION OUTPUT ;
    USE SIGNAL ;
    SHAPE ABUTMENT ;
    PORT
      LAYER M4 ;
      RECT 789.234 946.032 789.426 946.056 ;
    END
  END res_out[123]
  PIN res_out[124]
    DIRECTION OUTPUT ;
    USE SIGNAL ;
    SHAPE ABUTMENT ;
    PORT
      LAYER M4 ;
      RECT 789.234 947.904 789.426 947.928 ;
    END
  END res_out[124]
  PIN res_out[125]
    DIRECTION OUTPUT ;
    USE SIGNAL ;
    SHAPE ABUTMENT ;
    PORT
      LAYER M4 ;
      RECT 789.234 949.776 789.426 949.800 ;
    END
  END res_out[125]
  PIN res_out[126]
    DIRECTION OUTPUT ;
    USE SIGNAL ;
    SHAPE ABUTMENT ;
    PORT
      LAYER M4 ;
      RECT 789.234 951.648 789.426 951.672 ;
    END
  END res_out[126]
  PIN res_out[127]
    DIRECTION OUTPUT ;
    USE SIGNAL ;
    SHAPE ABUTMENT ;
    PORT
      LAYER M4 ;
      RECT 789.234 953.520 789.426 953.544 ;
    END
  END res_out[127]
  PIN res_out[128]
    DIRECTION OUTPUT ;
    USE SIGNAL ;
    SHAPE ABUTMENT ;
    PORT
      LAYER M4 ;
      RECT 789.234 955.440 789.426 955.464 ;
    END
  END res_out[128]
  PIN res_out[129]
    DIRECTION OUTPUT ;
    USE SIGNAL ;
    SHAPE ABUTMENT ;
    PORT
      LAYER M4 ;
      RECT 789.234 957.312 789.426 957.336 ;
    END
  END res_out[129]
  PIN res_out[130]
    DIRECTION OUTPUT ;
    USE SIGNAL ;
    SHAPE ABUTMENT ;
    PORT
      LAYER M4 ;
      RECT 789.234 959.184 789.426 959.208 ;
    END
  END res_out[130]
  PIN res_out[131]
    DIRECTION OUTPUT ;
    USE SIGNAL ;
    SHAPE ABUTMENT ;
    PORT
      LAYER M4 ;
      RECT 789.234 961.056 789.426 961.080 ;
    END
  END res_out[131]
  PIN res_out[132]
    DIRECTION OUTPUT ;
    USE SIGNAL ;
    SHAPE ABUTMENT ;
    PORT
      LAYER M4 ;
      RECT 789.234 962.928 789.426 962.952 ;
    END
  END res_out[132]
  PIN res_out[133]
    DIRECTION OUTPUT ;
    USE SIGNAL ;
    SHAPE ABUTMENT ;
    PORT
      LAYER M4 ;
      RECT 789.234 964.800 789.426 964.824 ;
    END
  END res_out[133]
  PIN res_out[134]
    DIRECTION OUTPUT ;
    USE SIGNAL ;
    SHAPE ABUTMENT ;
    PORT
      LAYER M4 ;
      RECT 789.234 966.720 789.426 966.744 ;
    END
  END res_out[134]
  PIN res_out[135]
    DIRECTION OUTPUT ;
    USE SIGNAL ;
    SHAPE ABUTMENT ;
    PORT
      LAYER M4 ;
      RECT 789.234 968.592 789.426 968.616 ;
    END
  END res_out[135]
  PIN res_out[136]
    DIRECTION OUTPUT ;
    USE SIGNAL ;
    SHAPE ABUTMENT ;
    PORT
      LAYER M4 ;
      RECT 789.234 970.464 789.426 970.488 ;
    END
  END res_out[136]
  PIN res_out[137]
    DIRECTION OUTPUT ;
    USE SIGNAL ;
    SHAPE ABUTMENT ;
    PORT
      LAYER M4 ;
      RECT 789.234 972.336 789.426 972.360 ;
    END
  END res_out[137]
  PIN res_out[138]
    DIRECTION OUTPUT ;
    USE SIGNAL ;
    SHAPE ABUTMENT ;
    PORT
      LAYER M4 ;
      RECT 789.234 974.208 789.426 974.232 ;
    END
  END res_out[138]
  PIN res_out[139]
    DIRECTION OUTPUT ;
    USE SIGNAL ;
    SHAPE ABUTMENT ;
    PORT
      LAYER M4 ;
      RECT 789.234 976.080 789.426 976.104 ;
    END
  END res_out[139]
  PIN VSS
    DIRECTION INOUT ;
    USE GROUND ;
    PORT
      LAYER M4 ;
      RECT 0.492 1.200 788.934 1.296 ;
      RECT 0.492 3.600 788.934 3.696 ;
      RECT 0.492 6.000 788.934 6.096 ;
      RECT 0.492 8.400 788.934 8.496 ;
      RECT 0.492 10.800 788.934 10.896 ;
      RECT 0.492 13.200 788.934 13.296 ;
      RECT 0.492 15.600 788.934 15.696 ;
      RECT 0.492 18.000 788.934 18.096 ;
      RECT 0.492 20.400 788.934 20.496 ;
      RECT 0.492 22.800 788.934 22.896 ;
      RECT 0.492 25.200 788.934 25.296 ;
      RECT 0.492 27.600 788.934 27.696 ;
      RECT 0.492 30.000 788.934 30.096 ;
      RECT 0.492 32.400 788.934 32.496 ;
      RECT 0.492 34.800 788.934 34.896 ;
      RECT 0.492 37.200 788.934 37.296 ;
      RECT 0.492 39.600 788.934 39.696 ;
      RECT 0.492 42.000 788.934 42.096 ;
      RECT 0.492 44.400 788.934 44.496 ;
      RECT 0.492 46.800 788.934 46.896 ;
      RECT 0.492 49.200 788.934 49.296 ;
      RECT 0.492 51.600 788.934 51.696 ;
      RECT 0.492 54.000 788.934 54.096 ;
      RECT 0.492 56.400 788.934 56.496 ;
      RECT 0.492 58.800 788.934 58.896 ;
      RECT 0.492 61.200 788.934 61.296 ;
      RECT 0.492 63.600 788.934 63.696 ;
      RECT 0.492 66.000 788.934 66.096 ;
      RECT 0.492 68.400 788.934 68.496 ;
      RECT 0.492 70.800 788.934 70.896 ;
      RECT 0.492 73.200 788.934 73.296 ;
      RECT 0.492 75.600 788.934 75.696 ;
      RECT 0.492 78.000 788.934 78.096 ;
      RECT 0.492 80.400 788.934 80.496 ;
      RECT 0.492 82.800 788.934 82.896 ;
      RECT 0.492 85.200 788.934 85.296 ;
      RECT 0.492 87.600 788.934 87.696 ;
      RECT 0.492 90.000 788.934 90.096 ;
      RECT 0.492 92.400 788.934 92.496 ;
      RECT 0.492 94.800 788.934 94.896 ;
      RECT 0.492 97.200 788.934 97.296 ;
      RECT 0.492 99.600 788.934 99.696 ;
      RECT 0.492 102.000 788.934 102.096 ;
      RECT 0.492 104.400 788.934 104.496 ;
      RECT 0.492 106.800 788.934 106.896 ;
      RECT 0.492 109.200 788.934 109.296 ;
      RECT 0.492 111.600 788.934 111.696 ;
      RECT 0.492 114.000 788.934 114.096 ;
      RECT 0.492 116.400 788.934 116.496 ;
      RECT 0.492 118.800 788.934 118.896 ;
      RECT 0.492 121.200 788.934 121.296 ;
      RECT 0.492 123.600 788.934 123.696 ;
      RECT 0.492 126.000 788.934 126.096 ;
      RECT 0.492 128.400 788.934 128.496 ;
      RECT 0.492 130.800 788.934 130.896 ;
      RECT 0.492 133.200 788.934 133.296 ;
      RECT 0.492 135.600 788.934 135.696 ;
      RECT 0.492 138.000 788.934 138.096 ;
      RECT 0.492 140.400 788.934 140.496 ;
      RECT 0.492 142.800 788.934 142.896 ;
      RECT 0.492 145.200 788.934 145.296 ;
      RECT 0.492 147.600 788.934 147.696 ;
      RECT 0.492 150.000 788.934 150.096 ;
      RECT 0.492 152.400 788.934 152.496 ;
      RECT 0.492 154.800 788.934 154.896 ;
      RECT 0.492 157.200 788.934 157.296 ;
      RECT 0.492 159.600 788.934 159.696 ;
      RECT 0.492 162.000 788.934 162.096 ;
      RECT 0.492 164.400 788.934 164.496 ;
      RECT 0.492 166.800 788.934 166.896 ;
      RECT 0.492 169.200 788.934 169.296 ;
      RECT 0.492 171.600 788.934 171.696 ;
      RECT 0.492 174.000 788.934 174.096 ;
      RECT 0.492 176.400 788.934 176.496 ;
      RECT 0.492 178.800 788.934 178.896 ;
      RECT 0.492 181.200 788.934 181.296 ;
      RECT 0.492 183.600 788.934 183.696 ;
      RECT 0.492 186.000 788.934 186.096 ;
      RECT 0.492 188.400 788.934 188.496 ;
      RECT 0.492 190.800 788.934 190.896 ;
      RECT 0.492 193.200 788.934 193.296 ;
      RECT 0.492 195.600 788.934 195.696 ;
      RECT 0.492 198.000 788.934 198.096 ;
      RECT 0.492 200.400 788.934 200.496 ;
      RECT 0.492 202.800 788.934 202.896 ;
      RECT 0.492 205.200 788.934 205.296 ;
      RECT 0.492 207.600 788.934 207.696 ;
      RECT 0.492 210.000 788.934 210.096 ;
      RECT 0.492 212.400 788.934 212.496 ;
      RECT 0.492 214.800 788.934 214.896 ;
      RECT 0.492 217.200 788.934 217.296 ;
      RECT 0.492 219.600 788.934 219.696 ;
      RECT 0.492 222.000 788.934 222.096 ;
      RECT 0.492 224.400 788.934 224.496 ;
      RECT 0.492 226.800 788.934 226.896 ;
      RECT 0.492 229.200 788.934 229.296 ;
      RECT 0.492 231.600 788.934 231.696 ;
      RECT 0.492 234.000 788.934 234.096 ;
      RECT 0.492 236.400 788.934 236.496 ;
      RECT 0.492 238.800 788.934 238.896 ;
      RECT 0.492 241.200 788.934 241.296 ;
      RECT 0.492 243.600 788.934 243.696 ;
      RECT 0.492 246.000 788.934 246.096 ;
      RECT 0.492 248.400 788.934 248.496 ;
      RECT 0.492 250.800 788.934 250.896 ;
      RECT 0.492 253.200 788.934 253.296 ;
      RECT 0.492 255.600 788.934 255.696 ;
      RECT 0.492 258.000 788.934 258.096 ;
      RECT 0.492 260.400 788.934 260.496 ;
      RECT 0.492 262.800 788.934 262.896 ;
      RECT 0.492 265.200 788.934 265.296 ;
      RECT 0.492 267.600 788.934 267.696 ;
      RECT 0.492 270.000 788.934 270.096 ;
      RECT 0.492 272.400 788.934 272.496 ;
      RECT 0.492 274.800 788.934 274.896 ;
      RECT 0.492 277.200 788.934 277.296 ;
      RECT 0.492 279.600 788.934 279.696 ;
      RECT 0.492 282.000 788.934 282.096 ;
      RECT 0.492 284.400 788.934 284.496 ;
      RECT 0.492 286.800 788.934 286.896 ;
      RECT 0.492 289.200 788.934 289.296 ;
      RECT 0.492 291.600 788.934 291.696 ;
      RECT 0.492 294.000 788.934 294.096 ;
      RECT 0.492 296.400 788.934 296.496 ;
      RECT 0.492 298.800 788.934 298.896 ;
      RECT 0.492 301.200 788.934 301.296 ;
      RECT 0.492 303.600 788.934 303.696 ;
      RECT 0.492 306.000 788.934 306.096 ;
      RECT 0.492 308.400 788.934 308.496 ;
      RECT 0.492 310.800 788.934 310.896 ;
      RECT 0.492 313.200 788.934 313.296 ;
      RECT 0.492 315.600 788.934 315.696 ;
      RECT 0.492 318.000 788.934 318.096 ;
      RECT 0.492 320.400 788.934 320.496 ;
      RECT 0.492 322.800 788.934 322.896 ;
      RECT 0.492 325.200 788.934 325.296 ;
      RECT 0.492 327.600 788.934 327.696 ;
      RECT 0.492 330.000 788.934 330.096 ;
      RECT 0.492 332.400 788.934 332.496 ;
      RECT 0.492 334.800 788.934 334.896 ;
      RECT 0.492 337.200 788.934 337.296 ;
      RECT 0.492 339.600 788.934 339.696 ;
      RECT 0.492 342.000 788.934 342.096 ;
      RECT 0.492 344.400 788.934 344.496 ;
      RECT 0.492 346.800 788.934 346.896 ;
      RECT 0.492 349.200 788.934 349.296 ;
      RECT 0.492 351.600 788.934 351.696 ;
      RECT 0.492 354.000 788.934 354.096 ;
      RECT 0.492 356.400 788.934 356.496 ;
      RECT 0.492 358.800 788.934 358.896 ;
      RECT 0.492 361.200 788.934 361.296 ;
      RECT 0.492 363.600 788.934 363.696 ;
      RECT 0.492 366.000 788.934 366.096 ;
      RECT 0.492 368.400 788.934 368.496 ;
      RECT 0.492 370.800 788.934 370.896 ;
      RECT 0.492 373.200 788.934 373.296 ;
      RECT 0.492 375.600 788.934 375.696 ;
      RECT 0.492 378.000 788.934 378.096 ;
      RECT 0.492 380.400 788.934 380.496 ;
      RECT 0.492 382.800 788.934 382.896 ;
      RECT 0.492 385.200 788.934 385.296 ;
      RECT 0.492 387.600 788.934 387.696 ;
      RECT 0.492 390.000 788.934 390.096 ;
      RECT 0.492 392.400 788.934 392.496 ;
      RECT 0.492 394.800 788.934 394.896 ;
      RECT 0.492 397.200 788.934 397.296 ;
      RECT 0.492 399.600 788.934 399.696 ;
      RECT 0.492 402.000 788.934 402.096 ;
      RECT 0.492 404.400 788.934 404.496 ;
      RECT 0.492 406.800 788.934 406.896 ;
      RECT 0.492 409.200 788.934 409.296 ;
      RECT 0.492 411.600 788.934 411.696 ;
      RECT 0.492 414.000 788.934 414.096 ;
      RECT 0.492 416.400 788.934 416.496 ;
      RECT 0.492 418.800 788.934 418.896 ;
      RECT 0.492 421.200 788.934 421.296 ;
      RECT 0.492 423.600 788.934 423.696 ;
      RECT 0.492 426.000 788.934 426.096 ;
      RECT 0.492 428.400 788.934 428.496 ;
      RECT 0.492 430.800 788.934 430.896 ;
      RECT 0.492 433.200 788.934 433.296 ;
      RECT 0.492 435.600 788.934 435.696 ;
      RECT 0.492 438.000 788.934 438.096 ;
      RECT 0.492 440.400 788.934 440.496 ;
      RECT 0.492 442.800 788.934 442.896 ;
      RECT 0.492 445.200 788.934 445.296 ;
      RECT 0.492 447.600 788.934 447.696 ;
      RECT 0.492 450.000 788.934 450.096 ;
      RECT 0.492 452.400 788.934 452.496 ;
      RECT 0.492 454.800 788.934 454.896 ;
      RECT 0.492 457.200 788.934 457.296 ;
      RECT 0.492 459.600 788.934 459.696 ;
      RECT 0.492 462.000 788.934 462.096 ;
      RECT 0.492 464.400 788.934 464.496 ;
      RECT 0.492 466.800 788.934 466.896 ;
      RECT 0.492 469.200 788.934 469.296 ;
      RECT 0.492 471.600 788.934 471.696 ;
      RECT 0.492 474.000 788.934 474.096 ;
      RECT 0.492 476.400 788.934 476.496 ;
      RECT 0.492 478.800 788.934 478.896 ;
      RECT 0.492 481.200 788.934 481.296 ;
      RECT 0.492 483.600 788.934 483.696 ;
      RECT 0.492 486.000 788.934 486.096 ;
      RECT 0.492 488.400 788.934 488.496 ;
      RECT 0.492 490.800 788.934 490.896 ;
      RECT 0.492 493.200 788.934 493.296 ;
      RECT 0.492 495.600 788.934 495.696 ;
      RECT 0.492 498.000 788.934 498.096 ;
      RECT 0.492 500.400 788.934 500.496 ;
      RECT 0.492 502.800 788.934 502.896 ;
      RECT 0.492 505.200 788.934 505.296 ;
      RECT 0.492 507.600 788.934 507.696 ;
      RECT 0.492 510.000 788.934 510.096 ;
      RECT 0.492 512.400 788.934 512.496 ;
      RECT 0.492 514.800 788.934 514.896 ;
      RECT 0.492 517.200 788.934 517.296 ;
      RECT 0.492 519.600 788.934 519.696 ;
      RECT 0.492 522.000 788.934 522.096 ;
      RECT 0.492 524.400 788.934 524.496 ;
      RECT 0.492 526.800 788.934 526.896 ;
      RECT 0.492 529.200 788.934 529.296 ;
      RECT 0.492 531.600 788.934 531.696 ;
      RECT 0.492 534.000 788.934 534.096 ;
      RECT 0.492 536.400 788.934 536.496 ;
      RECT 0.492 538.800 788.934 538.896 ;
      RECT 0.492 541.200 788.934 541.296 ;
      RECT 0.492 543.600 788.934 543.696 ;
      RECT 0.492 546.000 788.934 546.096 ;
      RECT 0.492 548.400 788.934 548.496 ;
      RECT 0.492 550.800 788.934 550.896 ;
      RECT 0.492 553.200 788.934 553.296 ;
      RECT 0.492 555.600 788.934 555.696 ;
      RECT 0.492 558.000 788.934 558.096 ;
      RECT 0.492 560.400 788.934 560.496 ;
      RECT 0.492 562.800 788.934 562.896 ;
      RECT 0.492 565.200 788.934 565.296 ;
      RECT 0.492 567.600 788.934 567.696 ;
      RECT 0.492 570.000 788.934 570.096 ;
      RECT 0.492 572.400 788.934 572.496 ;
      RECT 0.492 574.800 788.934 574.896 ;
      RECT 0.492 577.200 788.934 577.296 ;
      RECT 0.492 579.600 788.934 579.696 ;
      RECT 0.492 582.000 788.934 582.096 ;
      RECT 0.492 584.400 788.934 584.496 ;
      RECT 0.492 586.800 788.934 586.896 ;
      RECT 0.492 589.200 788.934 589.296 ;
      RECT 0.492 591.600 788.934 591.696 ;
      RECT 0.492 594.000 788.934 594.096 ;
      RECT 0.492 596.400 788.934 596.496 ;
      RECT 0.492 598.800 788.934 598.896 ;
      RECT 0.492 601.200 788.934 601.296 ;
      RECT 0.492 603.600 788.934 603.696 ;
      RECT 0.492 606.000 788.934 606.096 ;
      RECT 0.492 608.400 788.934 608.496 ;
      RECT 0.492 610.800 788.934 610.896 ;
      RECT 0.492 613.200 788.934 613.296 ;
      RECT 0.492 615.600 788.934 615.696 ;
      RECT 0.492 618.000 788.934 618.096 ;
      RECT 0.492 620.400 788.934 620.496 ;
      RECT 0.492 622.800 788.934 622.896 ;
      RECT 0.492 625.200 788.934 625.296 ;
      RECT 0.492 627.600 788.934 627.696 ;
      RECT 0.492 630.000 788.934 630.096 ;
      RECT 0.492 632.400 788.934 632.496 ;
      RECT 0.492 634.800 788.934 634.896 ;
      RECT 0.492 637.200 788.934 637.296 ;
      RECT 0.492 639.600 788.934 639.696 ;
      RECT 0.492 642.000 788.934 642.096 ;
      RECT 0.492 644.400 788.934 644.496 ;
      RECT 0.492 646.800 788.934 646.896 ;
      RECT 0.492 649.200 788.934 649.296 ;
      RECT 0.492 651.600 788.934 651.696 ;
      RECT 0.492 654.000 788.934 654.096 ;
      RECT 0.492 656.400 788.934 656.496 ;
      RECT 0.492 658.800 788.934 658.896 ;
      RECT 0.492 661.200 788.934 661.296 ;
      RECT 0.492 663.600 788.934 663.696 ;
      RECT 0.492 666.000 788.934 666.096 ;
      RECT 0.492 668.400 788.934 668.496 ;
      RECT 0.492 670.800 788.934 670.896 ;
      RECT 0.492 673.200 788.934 673.296 ;
      RECT 0.492 675.600 788.934 675.696 ;
      RECT 0.492 678.000 788.934 678.096 ;
      RECT 0.492 680.400 788.934 680.496 ;
      RECT 0.492 682.800 788.934 682.896 ;
      RECT 0.492 685.200 788.934 685.296 ;
      RECT 0.492 687.600 788.934 687.696 ;
      RECT 0.492 690.000 788.934 690.096 ;
      RECT 0.492 692.400 788.934 692.496 ;
      RECT 0.492 694.800 788.934 694.896 ;
      RECT 0.492 697.200 788.934 697.296 ;
      RECT 0.492 699.600 788.934 699.696 ;
      RECT 0.492 702.000 788.934 702.096 ;
      RECT 0.492 704.400 788.934 704.496 ;
      RECT 0.492 706.800 788.934 706.896 ;
      RECT 0.492 709.200 788.934 709.296 ;
      RECT 0.492 711.600 788.934 711.696 ;
      RECT 0.492 714.000 788.934 714.096 ;
      RECT 0.492 716.400 788.934 716.496 ;
      RECT 0.492 718.800 788.934 718.896 ;
      RECT 0.492 721.200 788.934 721.296 ;
      RECT 0.492 723.600 788.934 723.696 ;
      RECT 0.492 726.000 788.934 726.096 ;
      RECT 0.492 728.400 788.934 728.496 ;
      RECT 0.492 730.800 788.934 730.896 ;
      RECT 0.492 733.200 788.934 733.296 ;
      RECT 0.492 735.600 788.934 735.696 ;
      RECT 0.492 738.000 788.934 738.096 ;
      RECT 0.492 740.400 788.934 740.496 ;
      RECT 0.492 742.800 788.934 742.896 ;
      RECT 0.492 745.200 788.934 745.296 ;
      RECT 0.492 747.600 788.934 747.696 ;
      RECT 0.492 750.000 788.934 750.096 ;
      RECT 0.492 752.400 788.934 752.496 ;
      RECT 0.492 754.800 788.934 754.896 ;
      RECT 0.492 757.200 788.934 757.296 ;
      RECT 0.492 759.600 788.934 759.696 ;
      RECT 0.492 762.000 788.934 762.096 ;
      RECT 0.492 764.400 788.934 764.496 ;
      RECT 0.492 766.800 788.934 766.896 ;
      RECT 0.492 769.200 788.934 769.296 ;
      RECT 0.492 771.600 788.934 771.696 ;
      RECT 0.492 774.000 788.934 774.096 ;
      RECT 0.492 776.400 788.934 776.496 ;
      RECT 0.492 778.800 788.934 778.896 ;
      RECT 0.492 781.200 788.934 781.296 ;
      RECT 0.492 783.600 788.934 783.696 ;
      RECT 0.492 786.000 788.934 786.096 ;
      RECT 0.492 788.400 788.934 788.496 ;
      RECT 0.492 790.800 788.934 790.896 ;
      RECT 0.492 793.200 788.934 793.296 ;
      RECT 0.492 795.600 788.934 795.696 ;
      RECT 0.492 798.000 788.934 798.096 ;
      RECT 0.492 800.400 788.934 800.496 ;
      RECT 0.492 802.800 788.934 802.896 ;
      RECT 0.492 805.200 788.934 805.296 ;
      RECT 0.492 807.600 788.934 807.696 ;
      RECT 0.492 810.000 788.934 810.096 ;
      RECT 0.492 812.400 788.934 812.496 ;
      RECT 0.492 814.800 788.934 814.896 ;
      RECT 0.492 817.200 788.934 817.296 ;
      RECT 0.492 819.600 788.934 819.696 ;
      RECT 0.492 822.000 788.934 822.096 ;
      RECT 0.492 824.400 788.934 824.496 ;
      RECT 0.492 826.800 788.934 826.896 ;
      RECT 0.492 829.200 788.934 829.296 ;
      RECT 0.492 831.600 788.934 831.696 ;
      RECT 0.492 834.000 788.934 834.096 ;
      RECT 0.492 836.400 788.934 836.496 ;
      RECT 0.492 838.800 788.934 838.896 ;
      RECT 0.492 841.200 788.934 841.296 ;
      RECT 0.492 843.600 788.934 843.696 ;
      RECT 0.492 846.000 788.934 846.096 ;
      RECT 0.492 848.400 788.934 848.496 ;
      RECT 0.492 850.800 788.934 850.896 ;
      RECT 0.492 853.200 788.934 853.296 ;
      RECT 0.492 855.600 788.934 855.696 ;
      RECT 0.492 858.000 788.934 858.096 ;
      RECT 0.492 860.400 788.934 860.496 ;
      RECT 0.492 862.800 788.934 862.896 ;
      RECT 0.492 865.200 788.934 865.296 ;
      RECT 0.492 867.600 788.934 867.696 ;
      RECT 0.492 870.000 788.934 870.096 ;
      RECT 0.492 872.400 788.934 872.496 ;
      RECT 0.492 874.800 788.934 874.896 ;
      RECT 0.492 877.200 788.934 877.296 ;
      RECT 0.492 879.600 788.934 879.696 ;
      RECT 0.492 882.000 788.934 882.096 ;
      RECT 0.492 884.400 788.934 884.496 ;
      RECT 0.492 886.800 788.934 886.896 ;
      RECT 0.492 889.200 788.934 889.296 ;
      RECT 0.492 891.600 788.934 891.696 ;
      RECT 0.492 894.000 788.934 894.096 ;
      RECT 0.492 896.400 788.934 896.496 ;
      RECT 0.492 898.800 788.934 898.896 ;
      RECT 0.492 901.200 788.934 901.296 ;
      RECT 0.492 903.600 788.934 903.696 ;
      RECT 0.492 906.000 788.934 906.096 ;
      RECT 0.492 908.400 788.934 908.496 ;
      RECT 0.492 910.800 788.934 910.896 ;
      RECT 0.492 913.200 788.934 913.296 ;
      RECT 0.492 915.600 788.934 915.696 ;
      RECT 0.492 918.000 788.934 918.096 ;
      RECT 0.492 920.400 788.934 920.496 ;
      RECT 0.492 922.800 788.934 922.896 ;
      RECT 0.492 925.200 788.934 925.296 ;
      RECT 0.492 927.600 788.934 927.696 ;
      RECT 0.492 930.000 788.934 930.096 ;
      RECT 0.492 932.400 788.934 932.496 ;
      RECT 0.492 934.800 788.934 934.896 ;
      RECT 0.492 937.200 788.934 937.296 ;
      RECT 0.492 939.600 788.934 939.696 ;
      RECT 0.492 942.000 788.934 942.096 ;
      RECT 0.492 944.400 788.934 944.496 ;
      RECT 0.492 946.800 788.934 946.896 ;
      RECT 0.492 949.200 788.934 949.296 ;
      RECT 0.492 951.600 788.934 951.696 ;
      RECT 0.492 954.000 788.934 954.096 ;
      RECT 0.492 956.400 788.934 956.496 ;
      RECT 0.492 958.800 788.934 958.896 ;
      RECT 0.492 961.200 788.934 961.296 ;
      RECT 0.492 963.600 788.934 963.696 ;
      RECT 0.492 966.000 788.934 966.096 ;
      RECT 0.492 968.400 788.934 968.496 ;
      RECT 0.492 970.800 788.934 970.896 ;
      RECT 0.492 973.200 788.934 973.296 ;
      RECT 0.492 975.600 788.934 975.696 ;
    END
  END VSS
  PIN VDD
    DIRECTION INOUT ;
    USE POWER ;
    PORT
      LAYER M4 ;
      RECT 0.492 2.400 788.934 2.496 ;
      RECT 0.492 4.800 788.934 4.896 ;
      RECT 0.492 7.200 788.934 7.296 ;
      RECT 0.492 9.600 788.934 9.696 ;
      RECT 0.492 12.000 788.934 12.096 ;
      RECT 0.492 14.400 788.934 14.496 ;
      RECT 0.492 16.800 788.934 16.896 ;
      RECT 0.492 19.200 788.934 19.296 ;
      RECT 0.492 21.600 788.934 21.696 ;
      RECT 0.492 24.000 788.934 24.096 ;
      RECT 0.492 26.400 788.934 26.496 ;
      RECT 0.492 28.800 788.934 28.896 ;
      RECT 0.492 31.200 788.934 31.296 ;
      RECT 0.492 33.600 788.934 33.696 ;
      RECT 0.492 36.000 788.934 36.096 ;
      RECT 0.492 38.400 788.934 38.496 ;
      RECT 0.492 40.800 788.934 40.896 ;
      RECT 0.492 43.200 788.934 43.296 ;
      RECT 0.492 45.600 788.934 45.696 ;
      RECT 0.492 48.000 788.934 48.096 ;
      RECT 0.492 50.400 788.934 50.496 ;
      RECT 0.492 52.800 788.934 52.896 ;
      RECT 0.492 55.200 788.934 55.296 ;
      RECT 0.492 57.600 788.934 57.696 ;
      RECT 0.492 60.000 788.934 60.096 ;
      RECT 0.492 62.400 788.934 62.496 ;
      RECT 0.492 64.800 788.934 64.896 ;
      RECT 0.492 67.200 788.934 67.296 ;
      RECT 0.492 69.600 788.934 69.696 ;
      RECT 0.492 72.000 788.934 72.096 ;
      RECT 0.492 74.400 788.934 74.496 ;
      RECT 0.492 76.800 788.934 76.896 ;
      RECT 0.492 79.200 788.934 79.296 ;
      RECT 0.492 81.600 788.934 81.696 ;
      RECT 0.492 84.000 788.934 84.096 ;
      RECT 0.492 86.400 788.934 86.496 ;
      RECT 0.492 88.800 788.934 88.896 ;
      RECT 0.492 91.200 788.934 91.296 ;
      RECT 0.492 93.600 788.934 93.696 ;
      RECT 0.492 96.000 788.934 96.096 ;
      RECT 0.492 98.400 788.934 98.496 ;
      RECT 0.492 100.800 788.934 100.896 ;
      RECT 0.492 103.200 788.934 103.296 ;
      RECT 0.492 105.600 788.934 105.696 ;
      RECT 0.492 108.000 788.934 108.096 ;
      RECT 0.492 110.400 788.934 110.496 ;
      RECT 0.492 112.800 788.934 112.896 ;
      RECT 0.492 115.200 788.934 115.296 ;
      RECT 0.492 117.600 788.934 117.696 ;
      RECT 0.492 120.000 788.934 120.096 ;
      RECT 0.492 122.400 788.934 122.496 ;
      RECT 0.492 124.800 788.934 124.896 ;
      RECT 0.492 127.200 788.934 127.296 ;
      RECT 0.492 129.600 788.934 129.696 ;
      RECT 0.492 132.000 788.934 132.096 ;
      RECT 0.492 134.400 788.934 134.496 ;
      RECT 0.492 136.800 788.934 136.896 ;
      RECT 0.492 139.200 788.934 139.296 ;
      RECT 0.492 141.600 788.934 141.696 ;
      RECT 0.492 144.000 788.934 144.096 ;
      RECT 0.492 146.400 788.934 146.496 ;
      RECT 0.492 148.800 788.934 148.896 ;
      RECT 0.492 151.200 788.934 151.296 ;
      RECT 0.492 153.600 788.934 153.696 ;
      RECT 0.492 156.000 788.934 156.096 ;
      RECT 0.492 158.400 788.934 158.496 ;
      RECT 0.492 160.800 788.934 160.896 ;
      RECT 0.492 163.200 788.934 163.296 ;
      RECT 0.492 165.600 788.934 165.696 ;
      RECT 0.492 168.000 788.934 168.096 ;
      RECT 0.492 170.400 788.934 170.496 ;
      RECT 0.492 172.800 788.934 172.896 ;
      RECT 0.492 175.200 788.934 175.296 ;
      RECT 0.492 177.600 788.934 177.696 ;
      RECT 0.492 180.000 788.934 180.096 ;
      RECT 0.492 182.400 788.934 182.496 ;
      RECT 0.492 184.800 788.934 184.896 ;
      RECT 0.492 187.200 788.934 187.296 ;
      RECT 0.492 189.600 788.934 189.696 ;
      RECT 0.492 192.000 788.934 192.096 ;
      RECT 0.492 194.400 788.934 194.496 ;
      RECT 0.492 196.800 788.934 196.896 ;
      RECT 0.492 199.200 788.934 199.296 ;
      RECT 0.492 201.600 788.934 201.696 ;
      RECT 0.492 204.000 788.934 204.096 ;
      RECT 0.492 206.400 788.934 206.496 ;
      RECT 0.492 208.800 788.934 208.896 ;
      RECT 0.492 211.200 788.934 211.296 ;
      RECT 0.492 213.600 788.934 213.696 ;
      RECT 0.492 216.000 788.934 216.096 ;
      RECT 0.492 218.400 788.934 218.496 ;
      RECT 0.492 220.800 788.934 220.896 ;
      RECT 0.492 223.200 788.934 223.296 ;
      RECT 0.492 225.600 788.934 225.696 ;
      RECT 0.492 228.000 788.934 228.096 ;
      RECT 0.492 230.400 788.934 230.496 ;
      RECT 0.492 232.800 788.934 232.896 ;
      RECT 0.492 235.200 788.934 235.296 ;
      RECT 0.492 237.600 788.934 237.696 ;
      RECT 0.492 240.000 788.934 240.096 ;
      RECT 0.492 242.400 788.934 242.496 ;
      RECT 0.492 244.800 788.934 244.896 ;
      RECT 0.492 247.200 788.934 247.296 ;
      RECT 0.492 249.600 788.934 249.696 ;
      RECT 0.492 252.000 788.934 252.096 ;
      RECT 0.492 254.400 788.934 254.496 ;
      RECT 0.492 256.800 788.934 256.896 ;
      RECT 0.492 259.200 788.934 259.296 ;
      RECT 0.492 261.600 788.934 261.696 ;
      RECT 0.492 264.000 788.934 264.096 ;
      RECT 0.492 266.400 788.934 266.496 ;
      RECT 0.492 268.800 788.934 268.896 ;
      RECT 0.492 271.200 788.934 271.296 ;
      RECT 0.492 273.600 788.934 273.696 ;
      RECT 0.492 276.000 788.934 276.096 ;
      RECT 0.492 278.400 788.934 278.496 ;
      RECT 0.492 280.800 788.934 280.896 ;
      RECT 0.492 283.200 788.934 283.296 ;
      RECT 0.492 285.600 788.934 285.696 ;
      RECT 0.492 288.000 788.934 288.096 ;
      RECT 0.492 290.400 788.934 290.496 ;
      RECT 0.492 292.800 788.934 292.896 ;
      RECT 0.492 295.200 788.934 295.296 ;
      RECT 0.492 297.600 788.934 297.696 ;
      RECT 0.492 300.000 788.934 300.096 ;
      RECT 0.492 302.400 788.934 302.496 ;
      RECT 0.492 304.800 788.934 304.896 ;
      RECT 0.492 307.200 788.934 307.296 ;
      RECT 0.492 309.600 788.934 309.696 ;
      RECT 0.492 312.000 788.934 312.096 ;
      RECT 0.492 314.400 788.934 314.496 ;
      RECT 0.492 316.800 788.934 316.896 ;
      RECT 0.492 319.200 788.934 319.296 ;
      RECT 0.492 321.600 788.934 321.696 ;
      RECT 0.492 324.000 788.934 324.096 ;
      RECT 0.492 326.400 788.934 326.496 ;
      RECT 0.492 328.800 788.934 328.896 ;
      RECT 0.492 331.200 788.934 331.296 ;
      RECT 0.492 333.600 788.934 333.696 ;
      RECT 0.492 336.000 788.934 336.096 ;
      RECT 0.492 338.400 788.934 338.496 ;
      RECT 0.492 340.800 788.934 340.896 ;
      RECT 0.492 343.200 788.934 343.296 ;
      RECT 0.492 345.600 788.934 345.696 ;
      RECT 0.492 348.000 788.934 348.096 ;
      RECT 0.492 350.400 788.934 350.496 ;
      RECT 0.492 352.800 788.934 352.896 ;
      RECT 0.492 355.200 788.934 355.296 ;
      RECT 0.492 357.600 788.934 357.696 ;
      RECT 0.492 360.000 788.934 360.096 ;
      RECT 0.492 362.400 788.934 362.496 ;
      RECT 0.492 364.800 788.934 364.896 ;
      RECT 0.492 367.200 788.934 367.296 ;
      RECT 0.492 369.600 788.934 369.696 ;
      RECT 0.492 372.000 788.934 372.096 ;
      RECT 0.492 374.400 788.934 374.496 ;
      RECT 0.492 376.800 788.934 376.896 ;
      RECT 0.492 379.200 788.934 379.296 ;
      RECT 0.492 381.600 788.934 381.696 ;
      RECT 0.492 384.000 788.934 384.096 ;
      RECT 0.492 386.400 788.934 386.496 ;
      RECT 0.492 388.800 788.934 388.896 ;
      RECT 0.492 391.200 788.934 391.296 ;
      RECT 0.492 393.600 788.934 393.696 ;
      RECT 0.492 396.000 788.934 396.096 ;
      RECT 0.492 398.400 788.934 398.496 ;
      RECT 0.492 400.800 788.934 400.896 ;
      RECT 0.492 403.200 788.934 403.296 ;
      RECT 0.492 405.600 788.934 405.696 ;
      RECT 0.492 408.000 788.934 408.096 ;
      RECT 0.492 410.400 788.934 410.496 ;
      RECT 0.492 412.800 788.934 412.896 ;
      RECT 0.492 415.200 788.934 415.296 ;
      RECT 0.492 417.600 788.934 417.696 ;
      RECT 0.492 420.000 788.934 420.096 ;
      RECT 0.492 422.400 788.934 422.496 ;
      RECT 0.492 424.800 788.934 424.896 ;
      RECT 0.492 427.200 788.934 427.296 ;
      RECT 0.492 429.600 788.934 429.696 ;
      RECT 0.492 432.000 788.934 432.096 ;
      RECT 0.492 434.400 788.934 434.496 ;
      RECT 0.492 436.800 788.934 436.896 ;
      RECT 0.492 439.200 788.934 439.296 ;
      RECT 0.492 441.600 788.934 441.696 ;
      RECT 0.492 444.000 788.934 444.096 ;
      RECT 0.492 446.400 788.934 446.496 ;
      RECT 0.492 448.800 788.934 448.896 ;
      RECT 0.492 451.200 788.934 451.296 ;
      RECT 0.492 453.600 788.934 453.696 ;
      RECT 0.492 456.000 788.934 456.096 ;
      RECT 0.492 458.400 788.934 458.496 ;
      RECT 0.492 460.800 788.934 460.896 ;
      RECT 0.492 463.200 788.934 463.296 ;
      RECT 0.492 465.600 788.934 465.696 ;
      RECT 0.492 468.000 788.934 468.096 ;
      RECT 0.492 470.400 788.934 470.496 ;
      RECT 0.492 472.800 788.934 472.896 ;
      RECT 0.492 475.200 788.934 475.296 ;
      RECT 0.492 477.600 788.934 477.696 ;
      RECT 0.492 480.000 788.934 480.096 ;
      RECT 0.492 482.400 788.934 482.496 ;
      RECT 0.492 484.800 788.934 484.896 ;
      RECT 0.492 487.200 788.934 487.296 ;
      RECT 0.492 489.600 788.934 489.696 ;
      RECT 0.492 492.000 788.934 492.096 ;
      RECT 0.492 494.400 788.934 494.496 ;
      RECT 0.492 496.800 788.934 496.896 ;
      RECT 0.492 499.200 788.934 499.296 ;
      RECT 0.492 501.600 788.934 501.696 ;
      RECT 0.492 504.000 788.934 504.096 ;
      RECT 0.492 506.400 788.934 506.496 ;
      RECT 0.492 508.800 788.934 508.896 ;
      RECT 0.492 511.200 788.934 511.296 ;
      RECT 0.492 513.600 788.934 513.696 ;
      RECT 0.492 516.000 788.934 516.096 ;
      RECT 0.492 518.400 788.934 518.496 ;
      RECT 0.492 520.800 788.934 520.896 ;
      RECT 0.492 523.200 788.934 523.296 ;
      RECT 0.492 525.600 788.934 525.696 ;
      RECT 0.492 528.000 788.934 528.096 ;
      RECT 0.492 530.400 788.934 530.496 ;
      RECT 0.492 532.800 788.934 532.896 ;
      RECT 0.492 535.200 788.934 535.296 ;
      RECT 0.492 537.600 788.934 537.696 ;
      RECT 0.492 540.000 788.934 540.096 ;
      RECT 0.492 542.400 788.934 542.496 ;
      RECT 0.492 544.800 788.934 544.896 ;
      RECT 0.492 547.200 788.934 547.296 ;
      RECT 0.492 549.600 788.934 549.696 ;
      RECT 0.492 552.000 788.934 552.096 ;
      RECT 0.492 554.400 788.934 554.496 ;
      RECT 0.492 556.800 788.934 556.896 ;
      RECT 0.492 559.200 788.934 559.296 ;
      RECT 0.492 561.600 788.934 561.696 ;
      RECT 0.492 564.000 788.934 564.096 ;
      RECT 0.492 566.400 788.934 566.496 ;
      RECT 0.492 568.800 788.934 568.896 ;
      RECT 0.492 571.200 788.934 571.296 ;
      RECT 0.492 573.600 788.934 573.696 ;
      RECT 0.492 576.000 788.934 576.096 ;
      RECT 0.492 578.400 788.934 578.496 ;
      RECT 0.492 580.800 788.934 580.896 ;
      RECT 0.492 583.200 788.934 583.296 ;
      RECT 0.492 585.600 788.934 585.696 ;
      RECT 0.492 588.000 788.934 588.096 ;
      RECT 0.492 590.400 788.934 590.496 ;
      RECT 0.492 592.800 788.934 592.896 ;
      RECT 0.492 595.200 788.934 595.296 ;
      RECT 0.492 597.600 788.934 597.696 ;
      RECT 0.492 600.000 788.934 600.096 ;
      RECT 0.492 602.400 788.934 602.496 ;
      RECT 0.492 604.800 788.934 604.896 ;
      RECT 0.492 607.200 788.934 607.296 ;
      RECT 0.492 609.600 788.934 609.696 ;
      RECT 0.492 612.000 788.934 612.096 ;
      RECT 0.492 614.400 788.934 614.496 ;
      RECT 0.492 616.800 788.934 616.896 ;
      RECT 0.492 619.200 788.934 619.296 ;
      RECT 0.492 621.600 788.934 621.696 ;
      RECT 0.492 624.000 788.934 624.096 ;
      RECT 0.492 626.400 788.934 626.496 ;
      RECT 0.492 628.800 788.934 628.896 ;
      RECT 0.492 631.200 788.934 631.296 ;
      RECT 0.492 633.600 788.934 633.696 ;
      RECT 0.492 636.000 788.934 636.096 ;
      RECT 0.492 638.400 788.934 638.496 ;
      RECT 0.492 640.800 788.934 640.896 ;
      RECT 0.492 643.200 788.934 643.296 ;
      RECT 0.492 645.600 788.934 645.696 ;
      RECT 0.492 648.000 788.934 648.096 ;
      RECT 0.492 650.400 788.934 650.496 ;
      RECT 0.492 652.800 788.934 652.896 ;
      RECT 0.492 655.200 788.934 655.296 ;
      RECT 0.492 657.600 788.934 657.696 ;
      RECT 0.492 660.000 788.934 660.096 ;
      RECT 0.492 662.400 788.934 662.496 ;
      RECT 0.492 664.800 788.934 664.896 ;
      RECT 0.492 667.200 788.934 667.296 ;
      RECT 0.492 669.600 788.934 669.696 ;
      RECT 0.492 672.000 788.934 672.096 ;
      RECT 0.492 674.400 788.934 674.496 ;
      RECT 0.492 676.800 788.934 676.896 ;
      RECT 0.492 679.200 788.934 679.296 ;
      RECT 0.492 681.600 788.934 681.696 ;
      RECT 0.492 684.000 788.934 684.096 ;
      RECT 0.492 686.400 788.934 686.496 ;
      RECT 0.492 688.800 788.934 688.896 ;
      RECT 0.492 691.200 788.934 691.296 ;
      RECT 0.492 693.600 788.934 693.696 ;
      RECT 0.492 696.000 788.934 696.096 ;
      RECT 0.492 698.400 788.934 698.496 ;
      RECT 0.492 700.800 788.934 700.896 ;
      RECT 0.492 703.200 788.934 703.296 ;
      RECT 0.492 705.600 788.934 705.696 ;
      RECT 0.492 708.000 788.934 708.096 ;
      RECT 0.492 710.400 788.934 710.496 ;
      RECT 0.492 712.800 788.934 712.896 ;
      RECT 0.492 715.200 788.934 715.296 ;
      RECT 0.492 717.600 788.934 717.696 ;
      RECT 0.492 720.000 788.934 720.096 ;
      RECT 0.492 722.400 788.934 722.496 ;
      RECT 0.492 724.800 788.934 724.896 ;
      RECT 0.492 727.200 788.934 727.296 ;
      RECT 0.492 729.600 788.934 729.696 ;
      RECT 0.492 732.000 788.934 732.096 ;
      RECT 0.492 734.400 788.934 734.496 ;
      RECT 0.492 736.800 788.934 736.896 ;
      RECT 0.492 739.200 788.934 739.296 ;
      RECT 0.492 741.600 788.934 741.696 ;
      RECT 0.492 744.000 788.934 744.096 ;
      RECT 0.492 746.400 788.934 746.496 ;
      RECT 0.492 748.800 788.934 748.896 ;
      RECT 0.492 751.200 788.934 751.296 ;
      RECT 0.492 753.600 788.934 753.696 ;
      RECT 0.492 756.000 788.934 756.096 ;
      RECT 0.492 758.400 788.934 758.496 ;
      RECT 0.492 760.800 788.934 760.896 ;
      RECT 0.492 763.200 788.934 763.296 ;
      RECT 0.492 765.600 788.934 765.696 ;
      RECT 0.492 768.000 788.934 768.096 ;
      RECT 0.492 770.400 788.934 770.496 ;
      RECT 0.492 772.800 788.934 772.896 ;
      RECT 0.492 775.200 788.934 775.296 ;
      RECT 0.492 777.600 788.934 777.696 ;
      RECT 0.492 780.000 788.934 780.096 ;
      RECT 0.492 782.400 788.934 782.496 ;
      RECT 0.492 784.800 788.934 784.896 ;
      RECT 0.492 787.200 788.934 787.296 ;
      RECT 0.492 789.600 788.934 789.696 ;
      RECT 0.492 792.000 788.934 792.096 ;
      RECT 0.492 794.400 788.934 794.496 ;
      RECT 0.492 796.800 788.934 796.896 ;
      RECT 0.492 799.200 788.934 799.296 ;
      RECT 0.492 801.600 788.934 801.696 ;
      RECT 0.492 804.000 788.934 804.096 ;
      RECT 0.492 806.400 788.934 806.496 ;
      RECT 0.492 808.800 788.934 808.896 ;
      RECT 0.492 811.200 788.934 811.296 ;
      RECT 0.492 813.600 788.934 813.696 ;
      RECT 0.492 816.000 788.934 816.096 ;
      RECT 0.492 818.400 788.934 818.496 ;
      RECT 0.492 820.800 788.934 820.896 ;
      RECT 0.492 823.200 788.934 823.296 ;
      RECT 0.492 825.600 788.934 825.696 ;
      RECT 0.492 828.000 788.934 828.096 ;
      RECT 0.492 830.400 788.934 830.496 ;
      RECT 0.492 832.800 788.934 832.896 ;
      RECT 0.492 835.200 788.934 835.296 ;
      RECT 0.492 837.600 788.934 837.696 ;
      RECT 0.492 840.000 788.934 840.096 ;
      RECT 0.492 842.400 788.934 842.496 ;
      RECT 0.492 844.800 788.934 844.896 ;
      RECT 0.492 847.200 788.934 847.296 ;
      RECT 0.492 849.600 788.934 849.696 ;
      RECT 0.492 852.000 788.934 852.096 ;
      RECT 0.492 854.400 788.934 854.496 ;
      RECT 0.492 856.800 788.934 856.896 ;
      RECT 0.492 859.200 788.934 859.296 ;
      RECT 0.492 861.600 788.934 861.696 ;
      RECT 0.492 864.000 788.934 864.096 ;
      RECT 0.492 866.400 788.934 866.496 ;
      RECT 0.492 868.800 788.934 868.896 ;
      RECT 0.492 871.200 788.934 871.296 ;
      RECT 0.492 873.600 788.934 873.696 ;
      RECT 0.492 876.000 788.934 876.096 ;
      RECT 0.492 878.400 788.934 878.496 ;
      RECT 0.492 880.800 788.934 880.896 ;
      RECT 0.492 883.200 788.934 883.296 ;
      RECT 0.492 885.600 788.934 885.696 ;
      RECT 0.492 888.000 788.934 888.096 ;
      RECT 0.492 890.400 788.934 890.496 ;
      RECT 0.492 892.800 788.934 892.896 ;
      RECT 0.492 895.200 788.934 895.296 ;
      RECT 0.492 897.600 788.934 897.696 ;
      RECT 0.492 900.000 788.934 900.096 ;
      RECT 0.492 902.400 788.934 902.496 ;
      RECT 0.492 904.800 788.934 904.896 ;
      RECT 0.492 907.200 788.934 907.296 ;
      RECT 0.492 909.600 788.934 909.696 ;
      RECT 0.492 912.000 788.934 912.096 ;
      RECT 0.492 914.400 788.934 914.496 ;
      RECT 0.492 916.800 788.934 916.896 ;
      RECT 0.492 919.200 788.934 919.296 ;
      RECT 0.492 921.600 788.934 921.696 ;
      RECT 0.492 924.000 788.934 924.096 ;
      RECT 0.492 926.400 788.934 926.496 ;
      RECT 0.492 928.800 788.934 928.896 ;
      RECT 0.492 931.200 788.934 931.296 ;
      RECT 0.492 933.600 788.934 933.696 ;
      RECT 0.492 936.000 788.934 936.096 ;
      RECT 0.492 938.400 788.934 938.496 ;
      RECT 0.492 940.800 788.934 940.896 ;
      RECT 0.492 943.200 788.934 943.296 ;
      RECT 0.492 945.600 788.934 945.696 ;
      RECT 0.492 948.000 788.934 948.096 ;
      RECT 0.492 950.400 788.934 950.496 ;
      RECT 0.492 952.800 788.934 952.896 ;
      RECT 0.492 955.200 788.934 955.296 ;
      RECT 0.492 957.600 788.934 957.696 ;
      RECT 0.492 960.000 788.934 960.096 ;
      RECT 0.492 962.400 788.934 962.496 ;
      RECT 0.492 964.800 788.934 964.896 ;
      RECT 0.492 967.200 788.934 967.296 ;
      RECT 0.492 969.600 788.934 969.696 ;
      RECT 0.492 972.000 788.934 972.096 ;
      RECT 0.492 974.400 788.934 974.496 ;
      RECT 0.492 976.800 788.934 976.896 ;
    END
  END VDD
  OBS
    LAYER M1 ;
    RECT 0 0 789.426 978.480 ;
    LAYER M2 ;
    RECT 0 0 789.426 978.480 ;
    LAYER M3 ;
    RECT 0 0 789.426 978.480 ;
    LAYER M4 ;
    RECT 0 0 789.426 978.480 ;
    LAYER M5 ;
    RECT 0 0 789.426 978.480 ;
    LAYER M6 ;
    RECT 0 0 789.426 978.480 ;
    LAYER M7 ;
    RECT 0 0 789.426 978.480 ;
  END
END ot_pdie_tile_io

END LIBRARY
